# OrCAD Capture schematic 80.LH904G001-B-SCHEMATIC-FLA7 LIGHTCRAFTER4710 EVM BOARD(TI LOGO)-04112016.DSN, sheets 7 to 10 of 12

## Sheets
7 P12: Cypress USB to I2C: size D
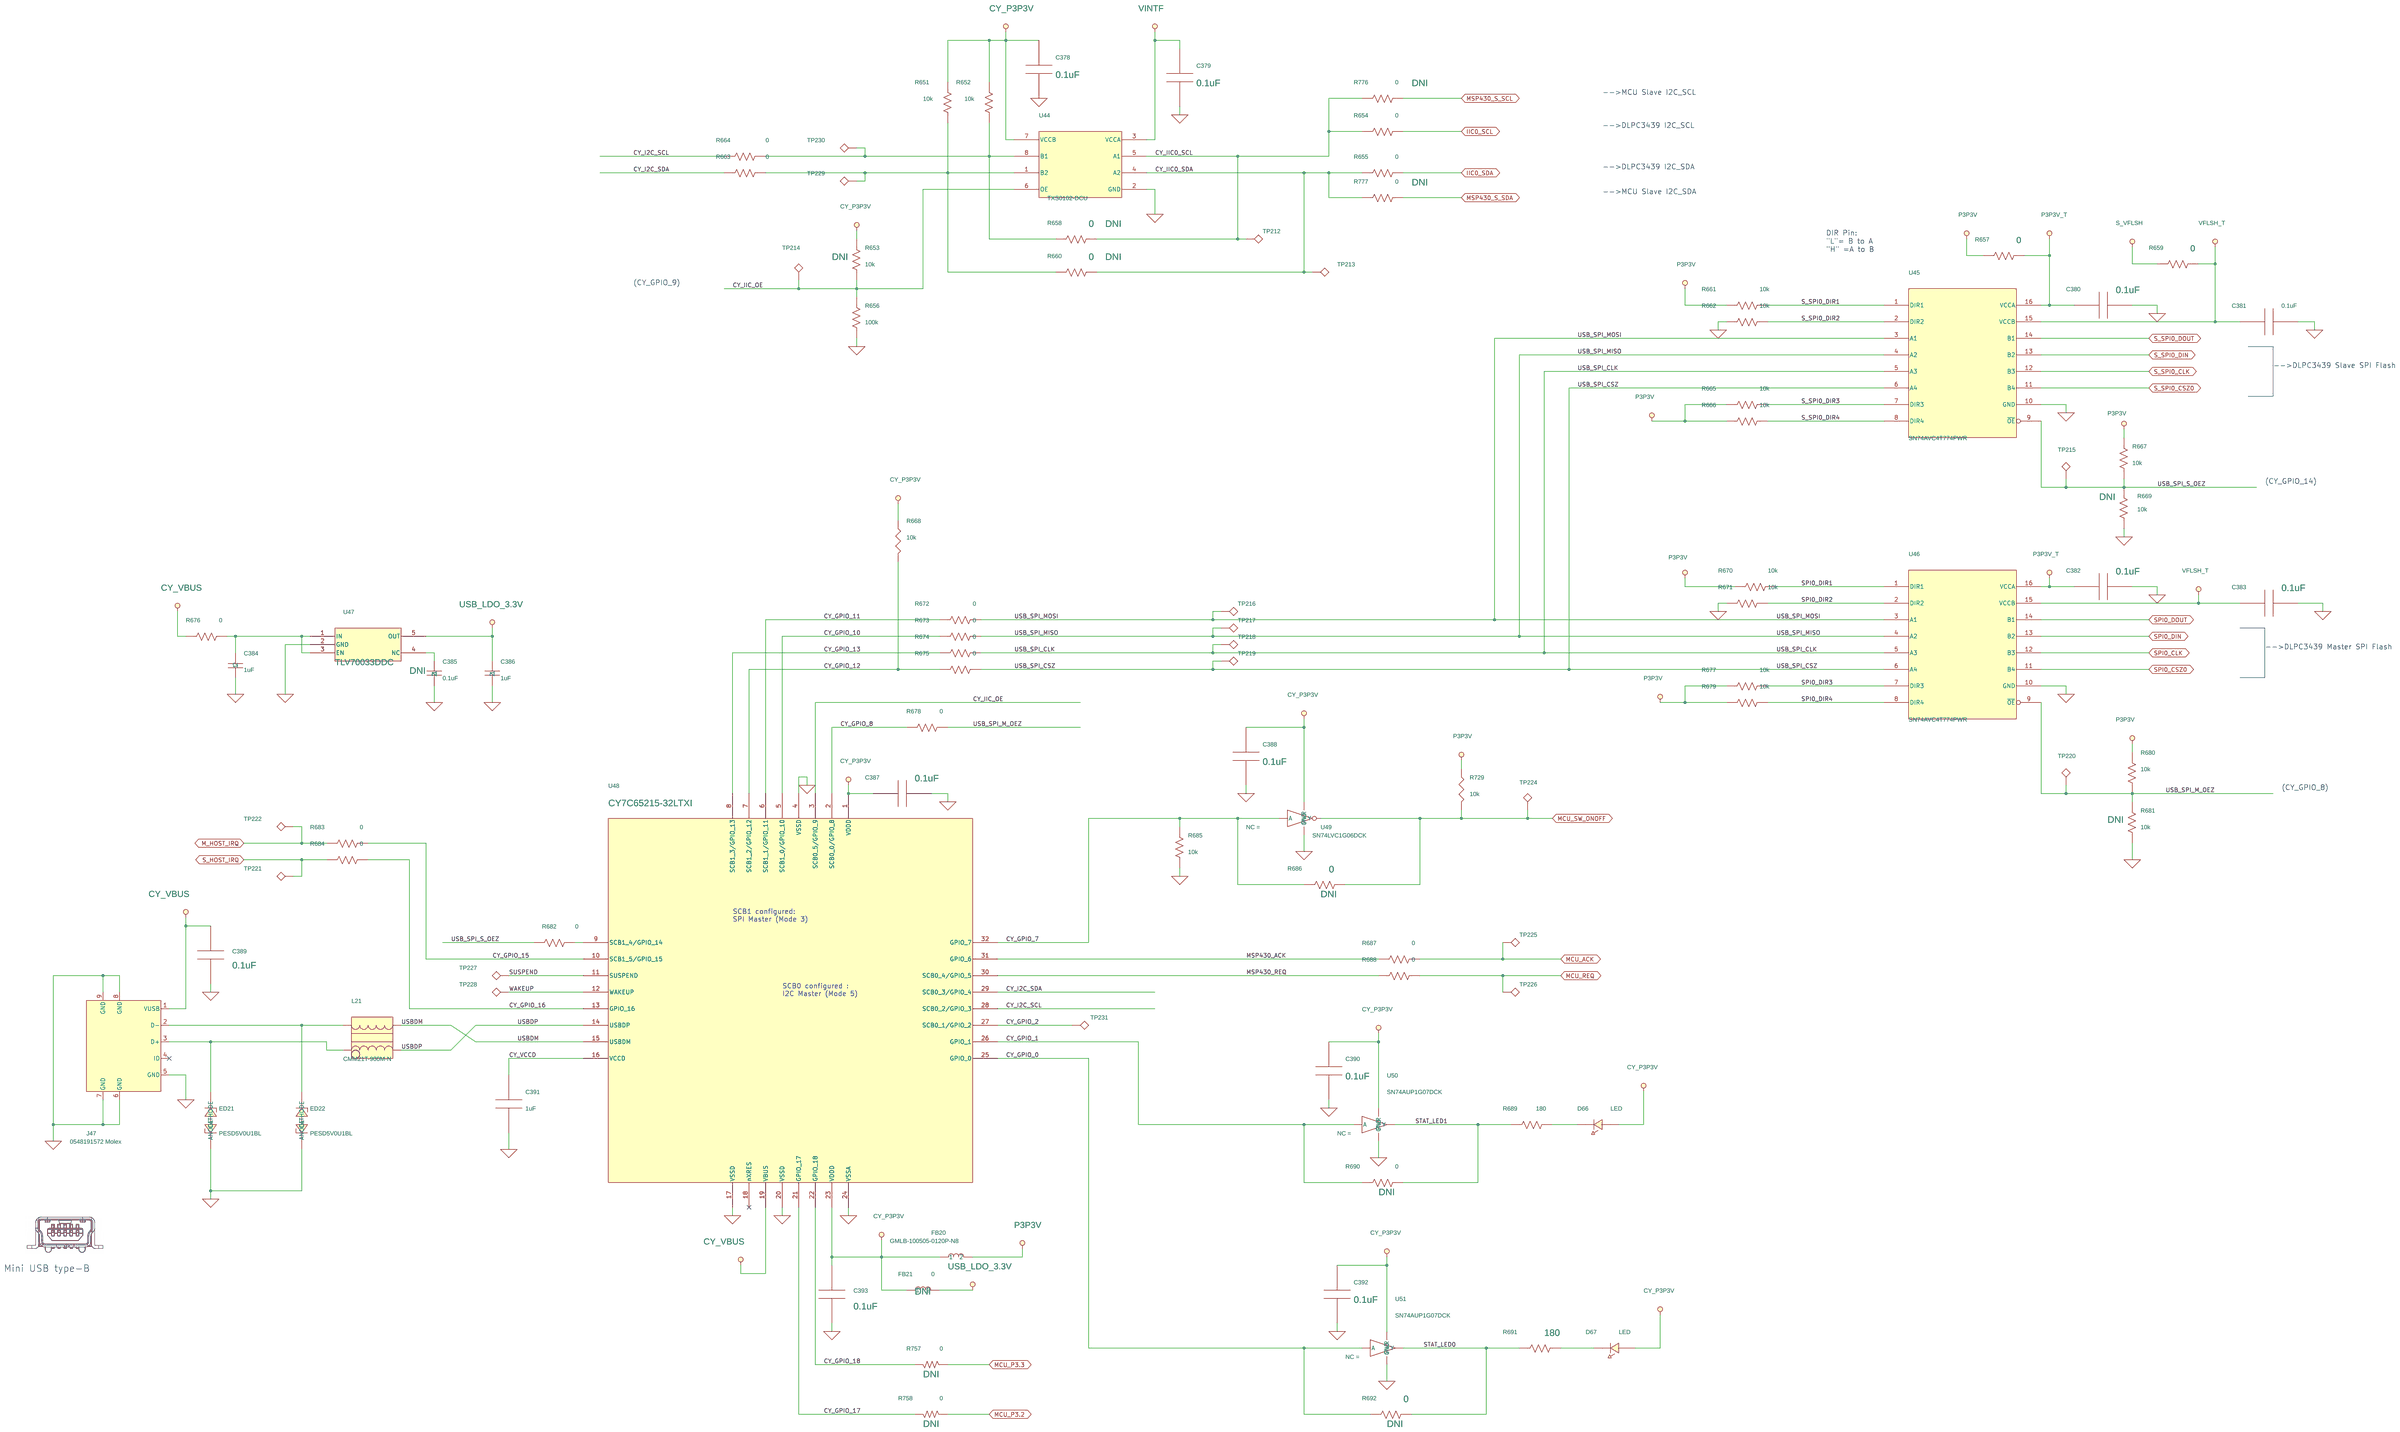
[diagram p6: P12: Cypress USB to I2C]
8 P11: Power supply and Fans: size D
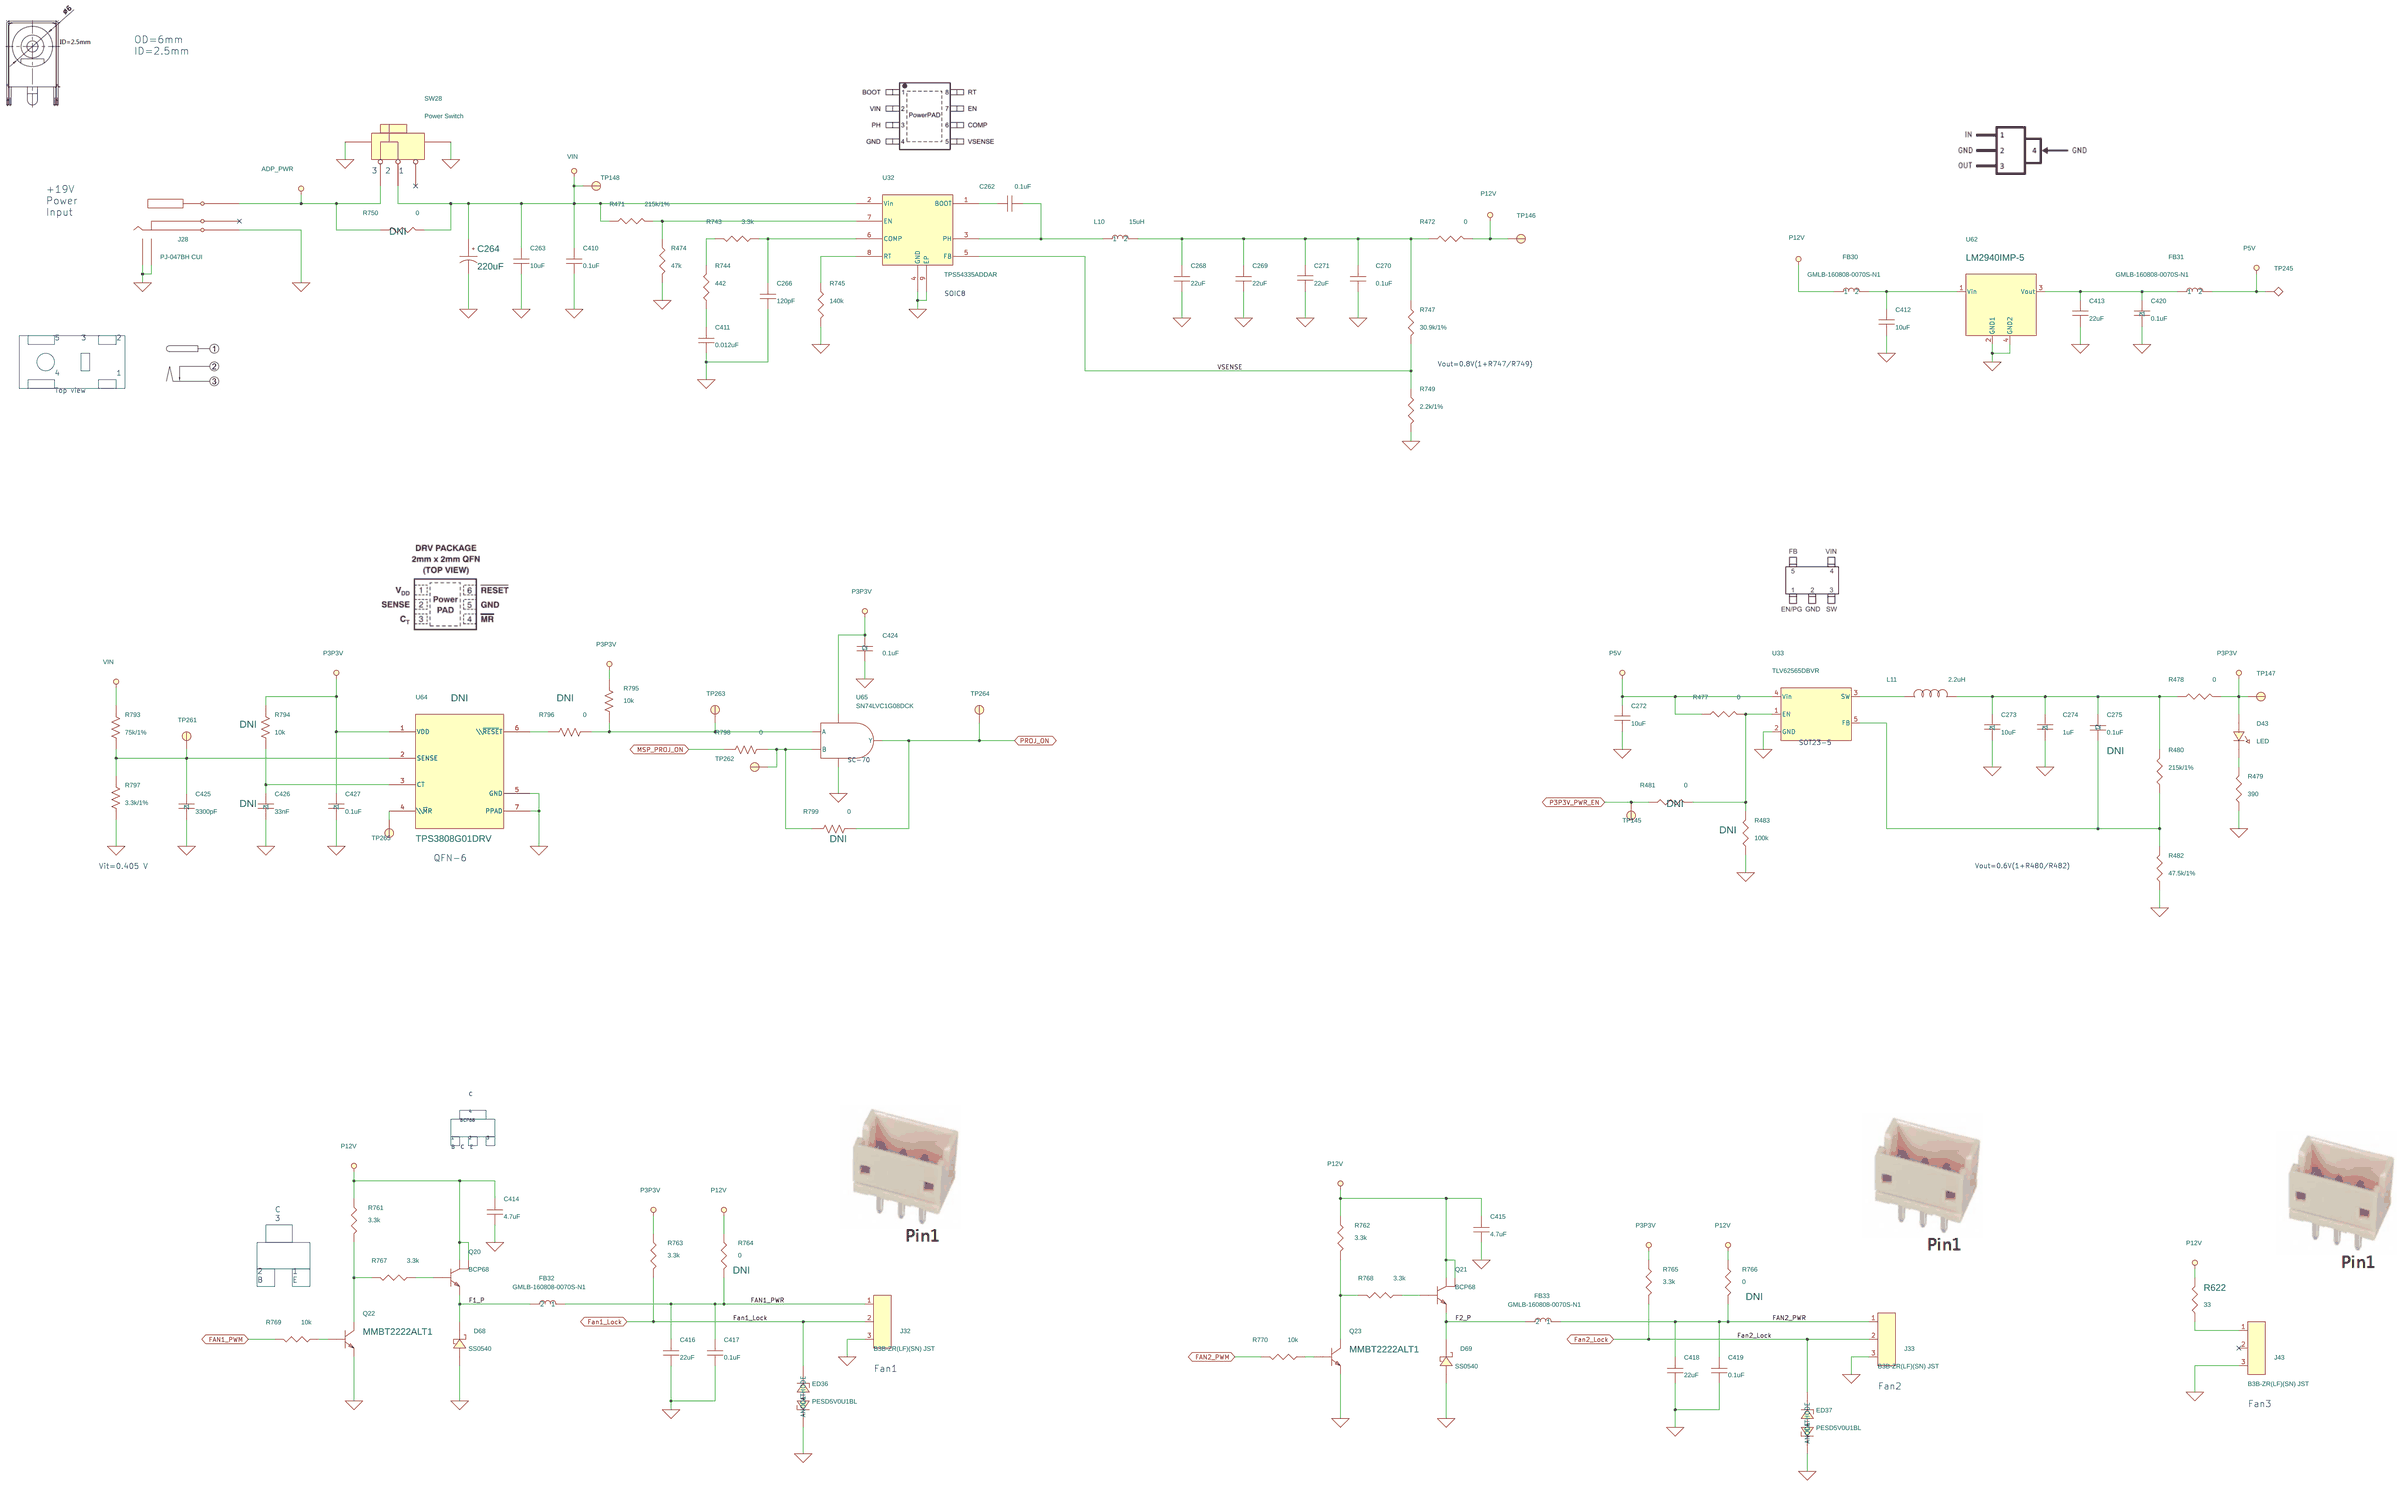
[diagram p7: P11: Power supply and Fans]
9 P04: DLPC3439_Video Input & DSI: size D
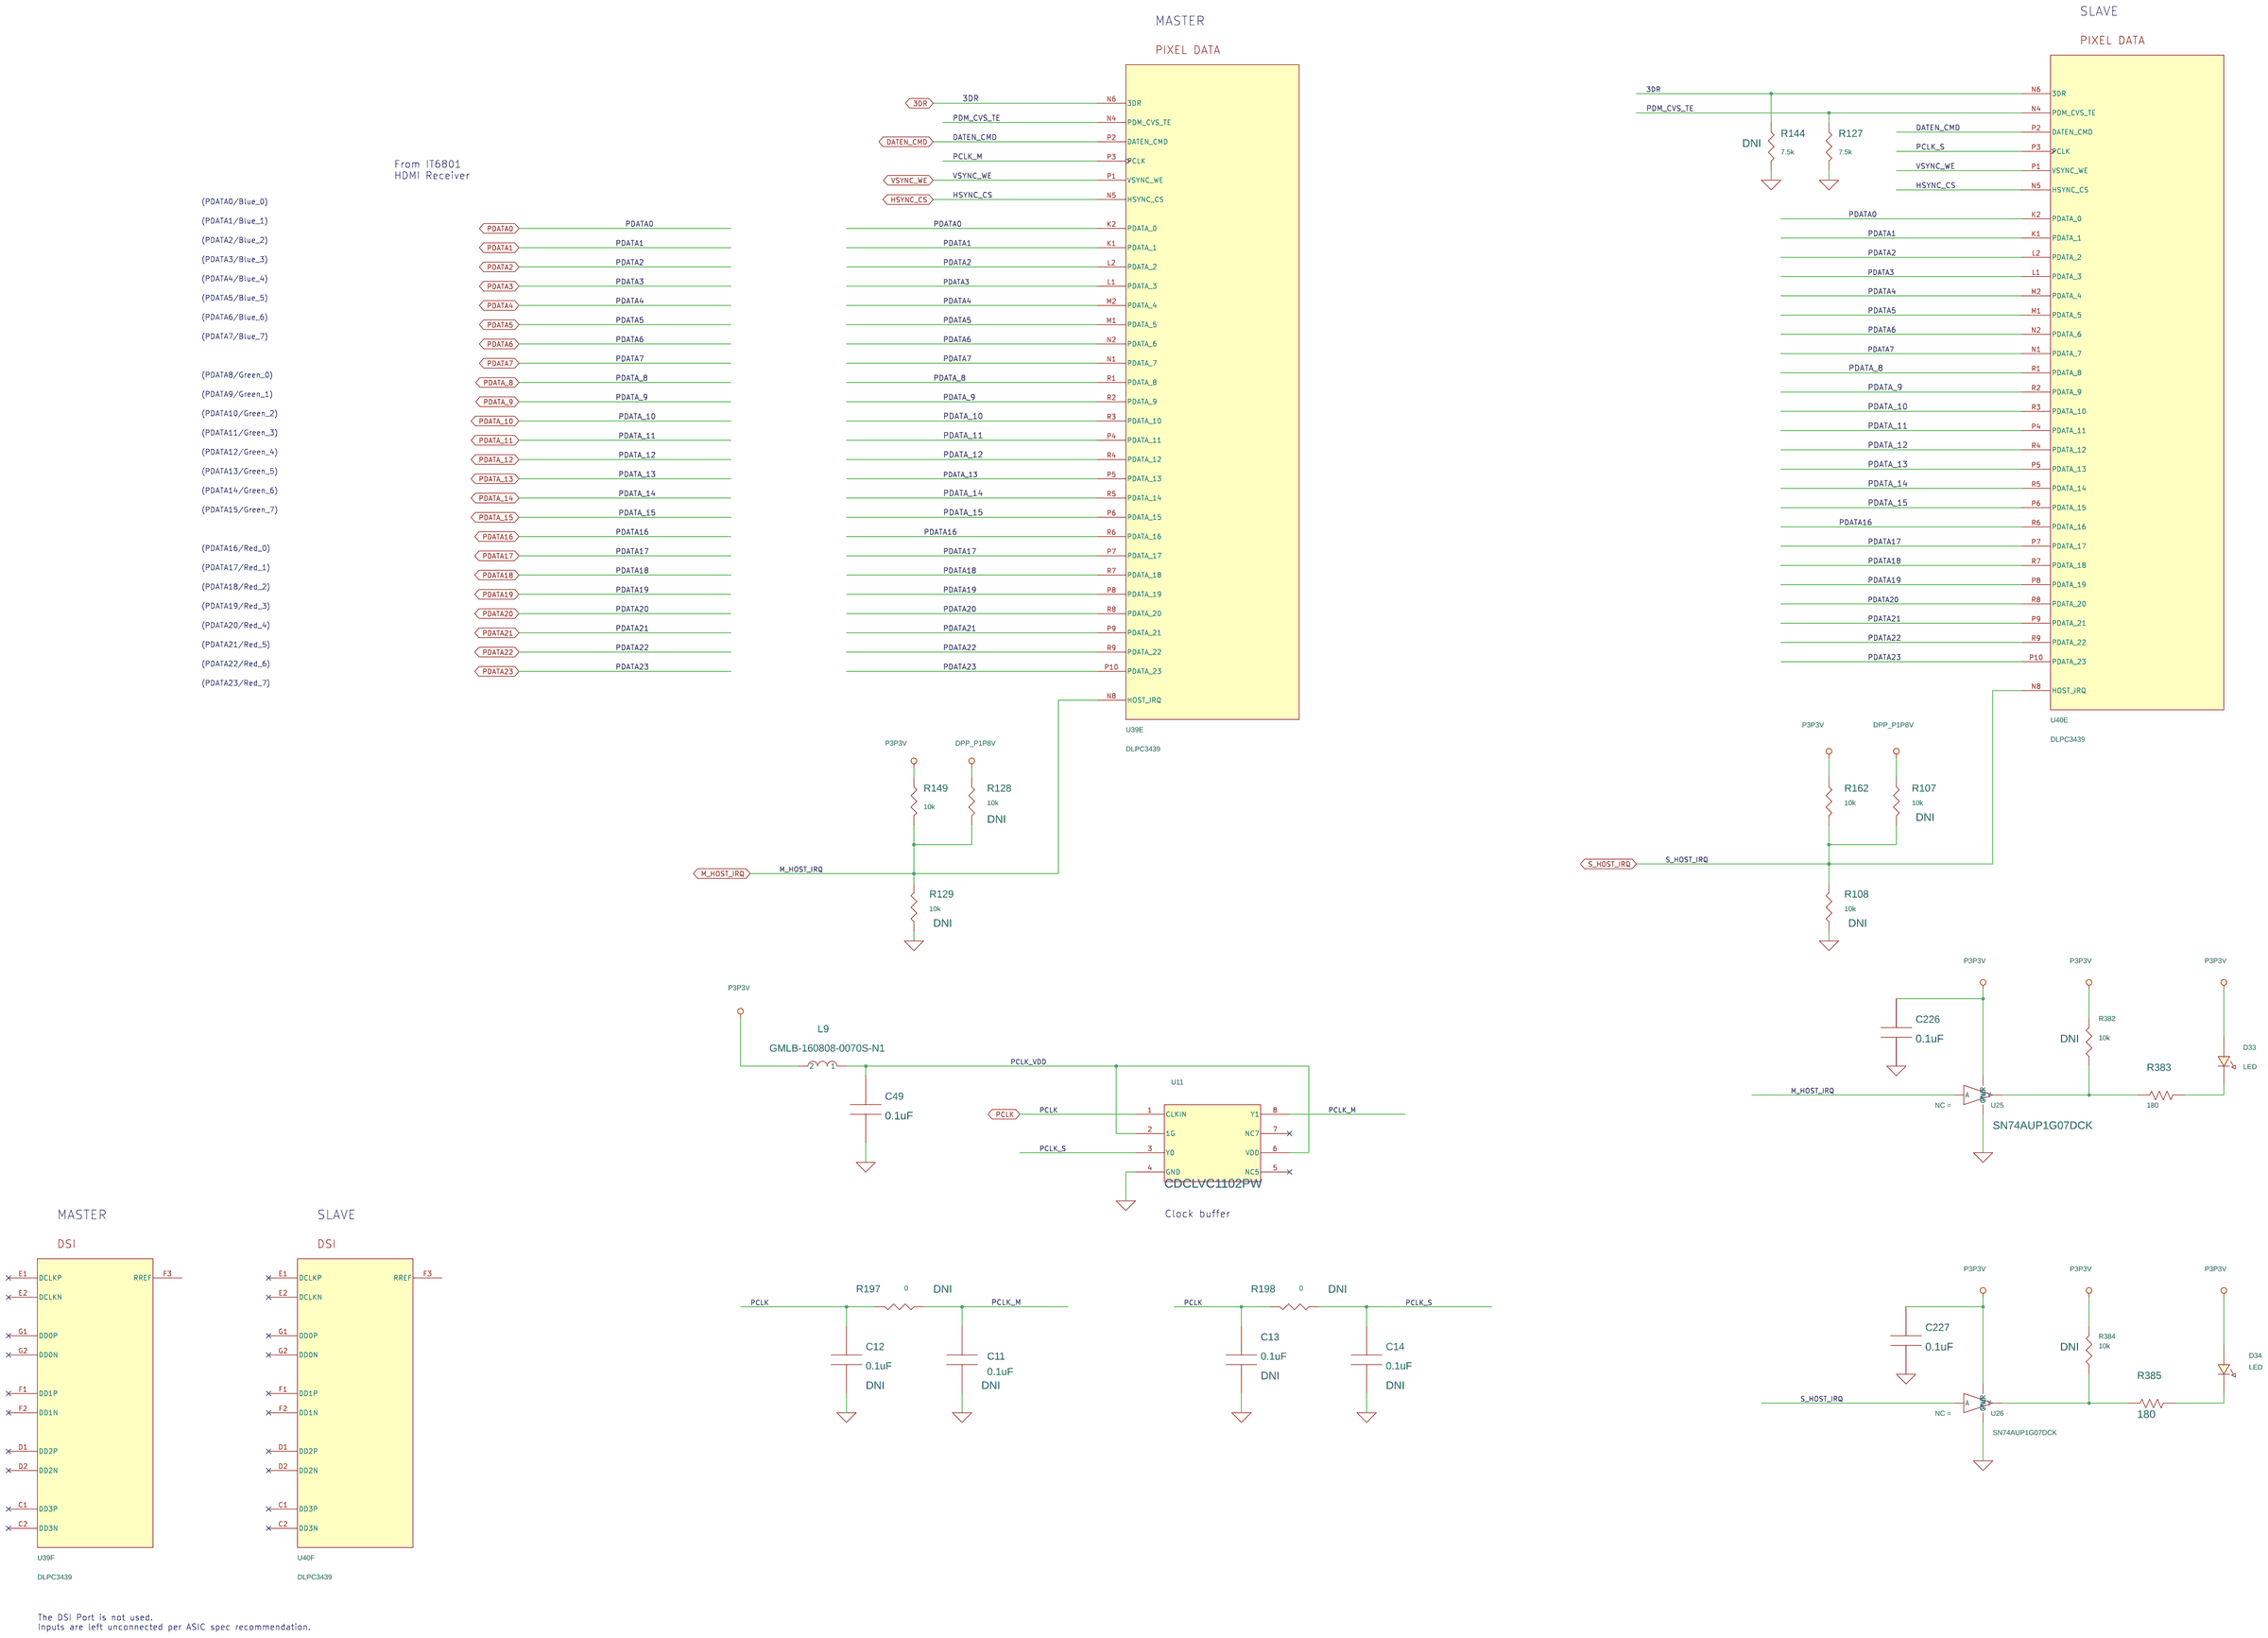
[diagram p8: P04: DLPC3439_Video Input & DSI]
10 P05: Dual DLPC343 & Flash,I2C: size D

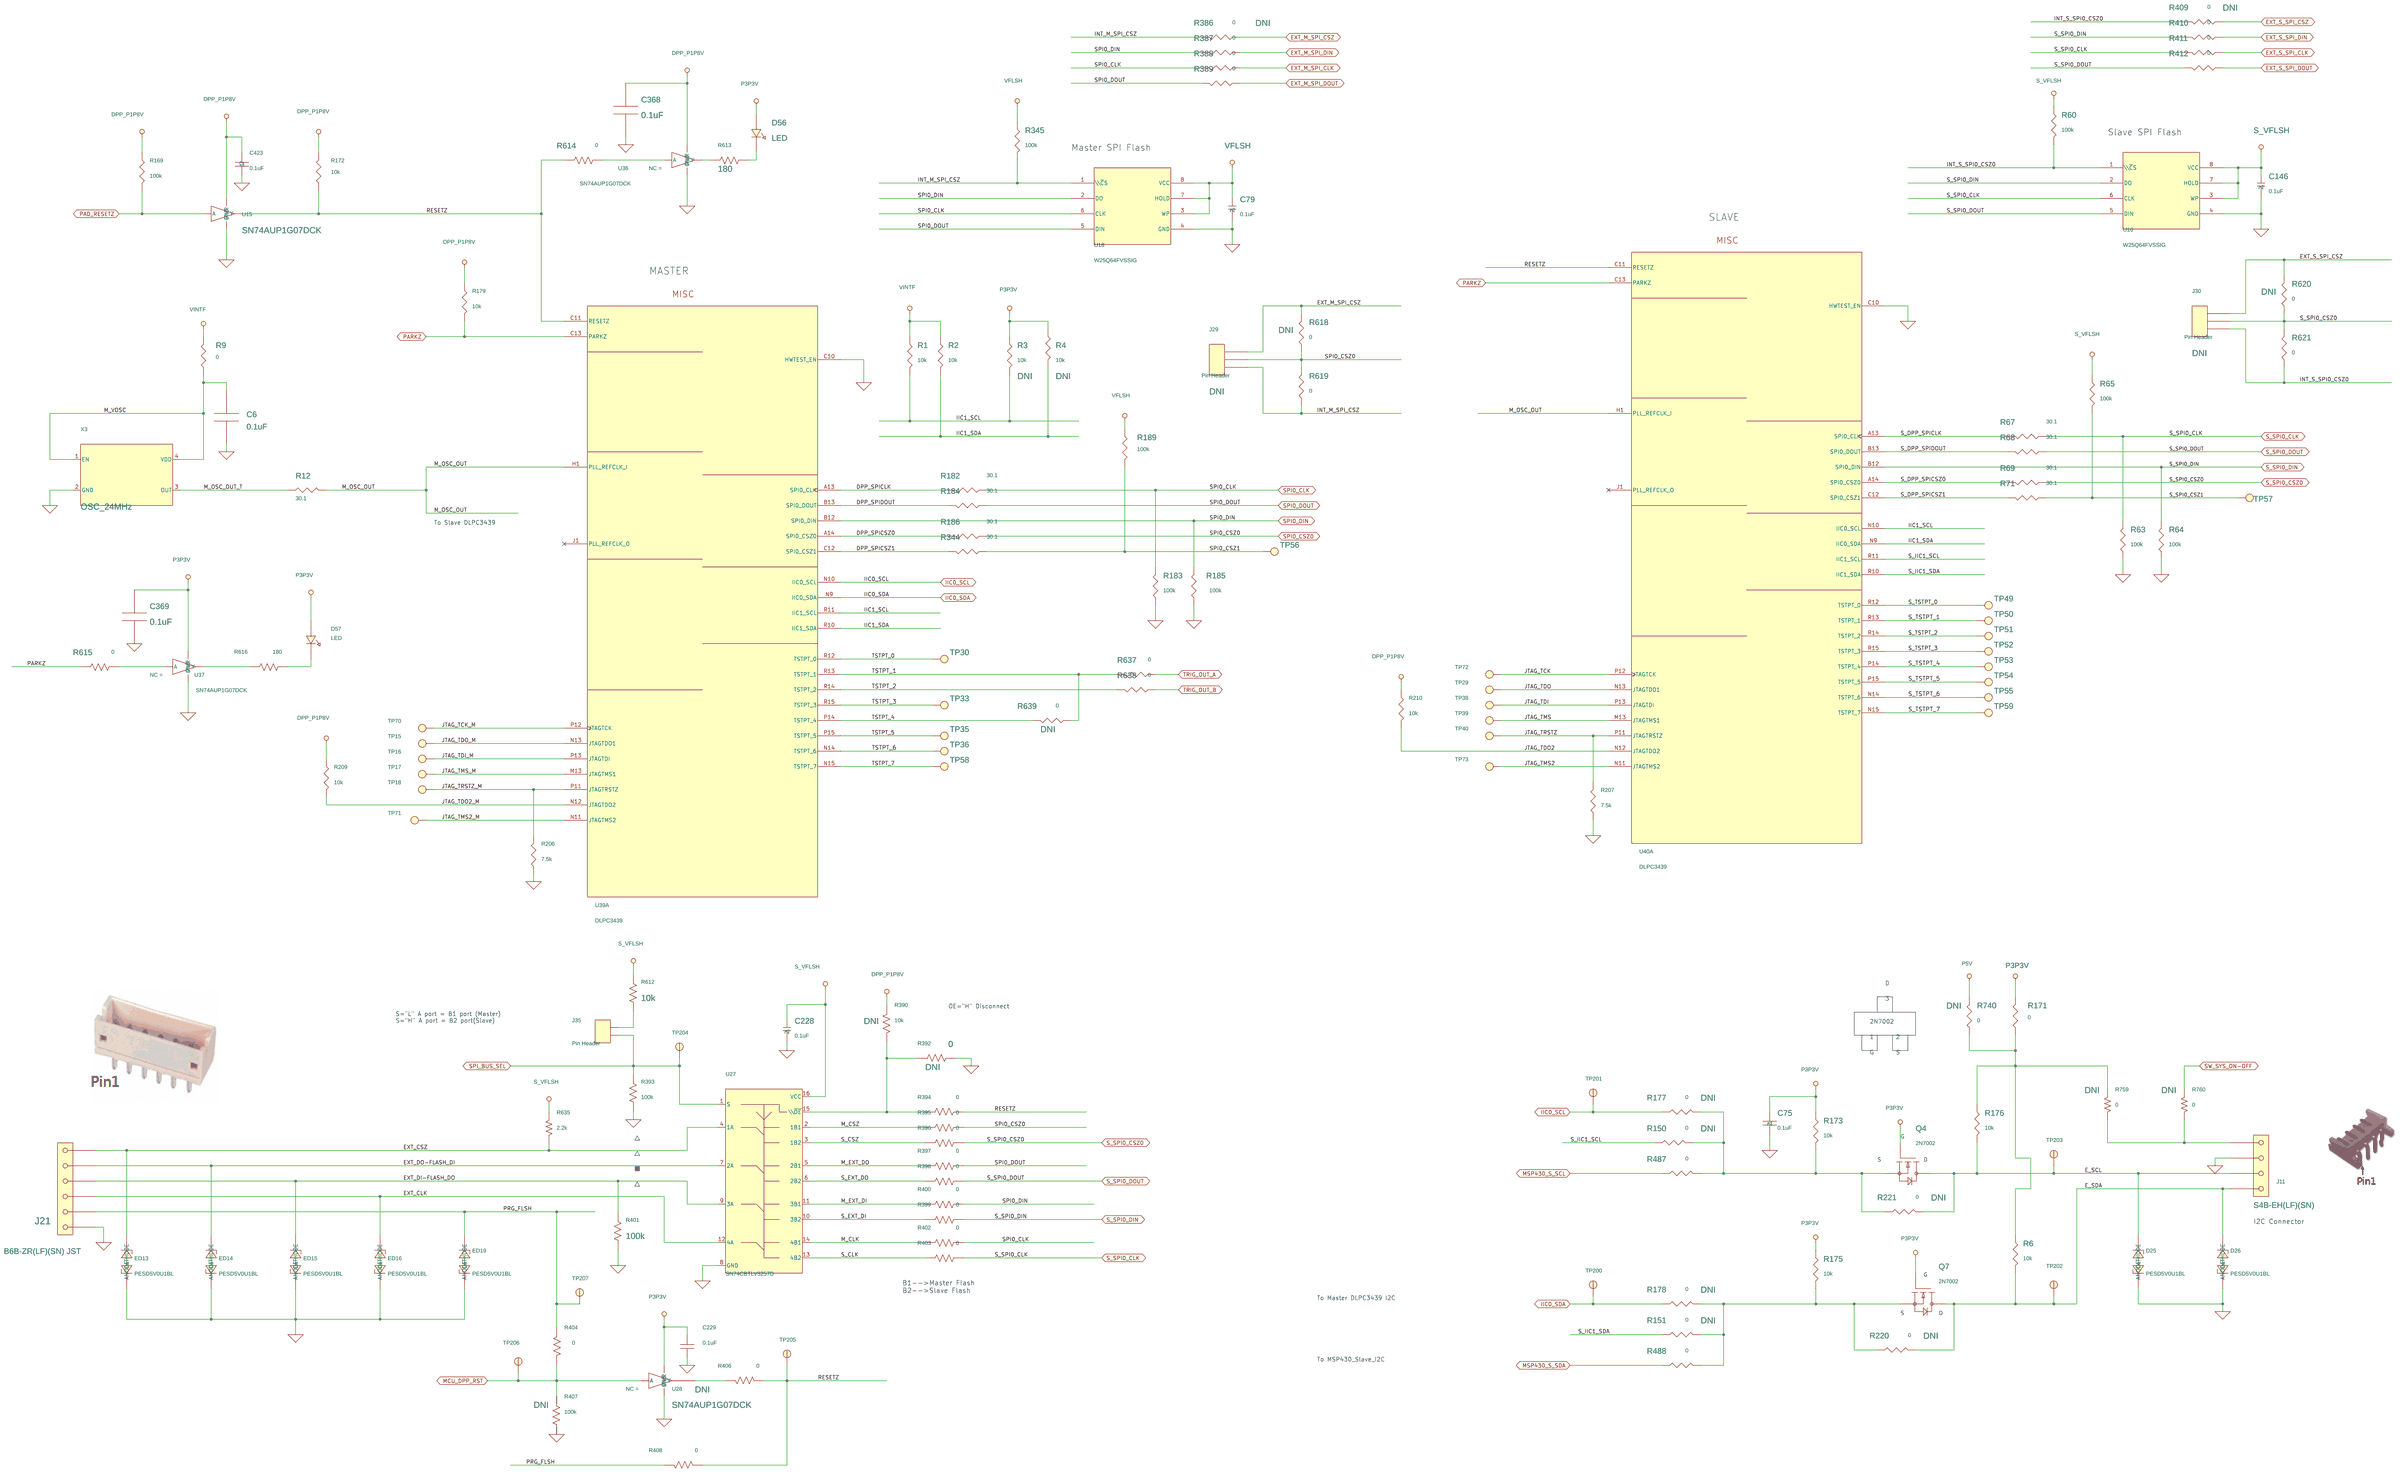
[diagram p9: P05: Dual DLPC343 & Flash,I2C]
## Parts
sheet P04: DLPC3439_Video Input & DSI
C11  0.1uF  [C0402\H0.55]
C12  0.1uF  [C0402\H0.55]
C13  0.1uF  [C0402\H0.55]
C14  0.1uF  [C0402\H0.55]
C49  0.1uF  [C0402\H0.55]
C226  0.1uF  [C0402\H0.55]
C227  0.1uF  [C0402\H0.55]
D33  LED  [LED2S\16-213\1X0.5\H0.45]
D34  LED  [LED2S\16-213\1X0.5\H0.45]
L9  GMLB-160808-0070S-N1  [L0603\H0.95]
R107  10k  [R0402\H0.4]
R108  10k  [R0402\H0.4]
R127  7.5k  [R0402\H0.4]
R128  10k  [R0402\H0.4]
R129  10k  [R0402\H0.4]
R144  7.5k  [R0402\H0.4]
R149  10k  [R0402\H0.4]
R162  10k  [R0402\H0.4]
R197  0  [R0402\H0.4]
R198  0  [R0402\H0.4]
R382  10k  [R0402\H0.4]
R383  180  [R0402\H0.4]
R384  10k  [R0402\H0.4]
R385  180  [R0402\H0.4]
U11  CDCLVC1102PW  [TSSOP8\0.65\H1.2]
U25  SN74AUP1G07DCK  [MCP5\0.65\H1.1]
U26  SN74AUP1G07DCK  [MCP5\0.65\H1.1]
sheet P05: Dual DLPC343 & Flash,I2C
C6  0.1uF  [C0402\H0.55]
C75  0.1uF  [C0402\H0.55]
C79  0.1uF  [C0201\H0.33]
C146  0.1uF  [C0201\H0.33]
C228  0.1uF  [C0201\H0.33]
C229  0.1uF  [C0402\H0.55]
C368  0.1uF  [C0402\H0.55]
C369  0.1uF  [C0402\H0.55]
C423  0.1uF  [C0402\H0.55]
D25  PESD5V0U1BL  [SOD882\2A1C\H0.5]
D26  PESD5V0U1BL  [SOD882\2A1C\H0.5]
D56  LED  [LED2S\16-213\1X0.5\H0.45]
D57  LED  [LED2S\16-213\1X0.5\H0.45]
ED13  PESD5V0U1BL  [SOD882\2A1C\H0.5]
ED14  PESD5V0U1BL  [SOD882\2A1C\H0.5]
ED15  PESD5V0U1BL  [SOD882\2A1C\H0.5]
ED16  PESD5V0U1BL  [SOD882\2A1C\H0.5]
ED19  PESD5V0U1BL  [SOD882\2A1C\H0.5]
J11  S4B-EH(LF)(SN)  [TU3007_4D_90\2.5\H4.8]
J21  B6B-ZR(LF)(SN) JST  [TU1501_6D_180\1.5\H4.5]
J29  Pin Header  [SIP3\2.54]
J30  Pin Header  [SIP3\2.54]
J35  Pin Header  [SIP2\2.54]
Q4  2N7002  [CP3\0.95\H1.11]
Q7  2N7002  [CP3\0.95\H1.11]
R1  10k  [R0402\H0.4]
R2  10k  [R0402\H0.4]
R3  10k  [R0402\H0.4]
R4  10k  [R0402\H0.4]
R6  10k  [R0402\H0.4]
R9  0  [R0402\H0.4]
R12  30.1  [R0402\H0.4]
R60  100k  [R0402\H0.4]
R63  100k  [R0402\H0.4]
R64  100k  [R0402\H0.4]
R65  100k  [R0402\H0.4]
R67  30.1  [R0402\H0.4]
R68  30.1  [R0402\H0.4]
R69  30.1  [R0402\H0.4]
R71  30.1  [R0402\H0.4]
R150  0  [R0402\H0.4]
R151  0  [R0402\H0.4]
R169  100k  [R0402\H0.4]
R171  0  [R0402\H0.4]
R172  10k  [R0402\H0.4]
R173  10k  [R0402\H0.4]
R175  10k  [R0402\H0.4]
R176  10k  [R0402\H0.4]
R177  0  [R0402\H0.4]
R178  0  [R0402\H0.4]
R179  10k  [R0402\H0.4]
R182  30.1  [R0402\H0.4]
R183  100k  [R0402\H0.4]
R184  30.1  [R0402\H0.4]
R185  100k  [R0402\H0.4]
R186  30.1  [R0402\H0.4]
R189  100k  [R0402\H0.4]
R206  7.5k  [R0402\H0.4]
R207  7.5k  [R0402\H0.4]
R209  10k  [R0402\H0.4]
R210  10k  [R0402\H0.4]
R220  0  [R0402\H0.4]
R221  0  [R0402\H0.4]
R344  30.1  [R0402\H0.4]
R345  100k  [R0402\H0.4]
R386  0  [R0402\H0.4]
R387  0  [R0402\H0.4]
R388  0  [R0402\H0.4]
R389  0  [R0402\H0.4]
R390  10k  [R0402\H0.4]
R392  0  [R0402\H0.4]
R393  100k  [R0402\H0.4]
R394  0  [R0402\H0.4]
R395  0  [R0402\H0.4]
R396  0  [R0402\H0.4]
R397  0  [R0402\H0.4]
R398  0  [R0402\H0.4]
R399  0  [R0402\H0.4]
R400  0  [R0402\H0.4]
R401  100k  [R0402\H0.4]
R402  0  [R0402\H0.4]
R403  0  [R0402\H0.4]
R404  0  [R0402\H0.4]
R406  0  [R0402\H0.4]
R407  100k  [R0402\H0.4]
R408  0  [R0402\H0.4]
R409  0  [R0402\H0.4]
R410  0  [R0402\H0.4]
R411  0  [R0402\H0.4]
R412  0  [R0402\H0.4]
R487  0  [R0402\H0.4]
R488  0  [R0402\H0.4]
R612  10k  [R0402\H0.4]
R613  180  [R0402\H0.4]
R614  0  [R0402\H0.4]
R615  0  [R0402\H0.4]
R616  180  [R0402\H0.4]
R618  0  [R0402\H0.4]
R619  0  [R0402\H0.4]
R620  0  [R0402\H0.4]
R621  0  [R0402\H0.4]
R635  2.2k  [R0402\H0.4]
R637  0  [R0402\H0.4]
R638  0  [R0402\H0.4]
R639  0  [R0402\H0.4]
R740  0  [R0402\H0.4]
R759  0  [R0402\H0.4]
R760  0  [R0402\H0.4]
TP15  Testpoint  [ICT_50]
TP16  Testpoint  [ICT_50]
TP17  Testpoint  [ICT_50]
TP18  Testpoint  [ICT_50]
TP29  Testpoint  [ICT_50]
TP30  Testpoint  [ICT_50]
TP33  Testpoint  [ICT_50]
TP35  Testpoint  [ICT_50]
TP36  Testpoint  [ICT_50]
TP38  Testpoint  [ICT_50]
TP39  Testpoint  [ICT_50]
TP40  Testpoint  [ICT_50]
TP49  Testpoint  [ICT_50]
TP50  Testpoint  [ICT_50]
TP51  Testpoint  [ICT_50]
TP52  Testpoint  [ICT_50]
TP53  Testpoint  [ICT_50]
TP54  Testpoint  [ICT_50]
TP55  Testpoint  [ICT_50]
TP56  Testpoint  [ICT_50]
TP57  Testpoint  [ICT_50]
TP58  Testpoint  [ICT_50]
TP59  Testpoint  [ICT_50]
TP70  Testpoint  [ICT_50]
TP71  Testpoint  [ICT_50]
TP72  Testpoint  [ICT_50]
TP73  Testpoint  [ICT_50]
TP200  Testpoint  [ICT_50]
TP201  Testpoint  [ICT_50]
TP202  Testpoint  [ICT_50]
TP203  Testpoint  [ICT_50]
TP204  Testpoint  [ICT_50]
TP205  Testpoint  [ICT_50]
TP206  Testpoint  [ICT_50]
TP207  Testpoint  [ICT_50]
U15  SN74AUP1G07DCK  [MCP5\0.65\H1.1]
U16  W25Q64FVSSIG  [SOP8A\1.27\H2.16]
U18  W25Q64FVSSIG  [SOP8A\1.27\H2.16]
U27  SN74CBTLV3257D  [SOP16A\1.27\H1.75]
U28  SN74AUP1G07DCK  [MCP5\0.65\H1.1]
U36  SN74AUP1G07DCK  [MCP5\0.65\H1.1]
U37  SN74AUP1G07DCK  [MCP5\0.65\H1.1]
X3  OSC_24MHz  [CRYS4\SO3225\3.2X2.5\H1.2]
sheet P06: DLPC3439_GPIO,LED_SEL,TRIG
U39  DLPC3439  [VFBGA201\0.8\H1]  (sections A,B,C,D,E,F,G,H)
U40  DLPC3439  [VFBGA201\0.8\H1]  (sections A,B,C,D,E,F,G,H)
sheet P11: Power supply and Fans
C262  0.1uF  [C0603\H0.9]
C263  10uF  [C1210\H2.8]
C264  220uF  [CS\MR10\H10.5]
C266  120pF  [C0402\H0.55]
C268  22uF  [C1210\H2.8]
C269  22uF  [C1210\H2.8]
C270  0.1uF  [C0402\H0.55]
C271  22uF  [C1210\H2.8]
C272  10uF  [C0603\H0.9]
C273  10uF  [C0603\H0.9]
C274  1uF  [C0402\H0.55]
C275  0.1uF  [C0402\H0.55]
C410  0.1uF  [C0603\H0.9]
C411  0.012uF  [C0603\H0.9]
C412  10uF  [C0805\H1.35]
C413  22uF  [C0805\H1.35]
C414  4.7uF  [C0805\H1.35]
C415  4.7uF  [C0805\H1.35]
C416  22uF  [C1210\H2.8]
C417  0.1uF  [C0402\H0.55]
C418  22uF  [C1210\H2.8]
C419  0.1uF  [C0402\H0.55]
C420  0.1uF  [C0402\H0.55]
C424  0.1uF  [C0402\H0.55]
C425  3300pF  [C0402\H0.55]
C426  33nF  [C0402\H0.55]
C427  0.1uF  [C0402\H0.55]
D43  LED  [LED2S\16-213\1X0.5\H0.45]
D68  SS0540  [SOD123\3.85X1.8\H1.35]
D69  SS0540  [SOD123\3.85X1.8\H1.35]
ED36  PESD5V0U1BL  [SOD882\2A1C\H0.5]
ED37  PESD5V0U1BL  [SOD882\2A1C\H0.5]
FB30  GMLB-160808-0070S-N1  [L0603\H0.95]
FB31  GMLB-160808-0070S-N1  [L0603\H0.95]
FB32  GMLB-160808-0070S-N1  [L0603\H0.95]
FB33  GMLB-160808-0070S-N1  [L0603\H0.95]
J28  PJ-047BH CUI  [DC-JACK3\IDJ-D40-D43B2\H9.6]
J32  B3B-ZR(LF)(SN) JST  [SSIP3\1.5\H4.5]
J33  B3B-ZR(LF)(SN) JST  [SSIP3\1.5\H4.5]
J43  B3B-ZR(LF)(SN) JST  [SSIP3\1.5\H4.5]
L10  15uH  [IND\MMD-10DZ\H4]
L11  2.2uH  [IND\3X3\H1.5]
Q20  BCP68  [SOT223\2.3\H1.8]
Q21  BCP68  [SOT223\2.3\H1.8]
Q22  MMBT2222ALT1  [CPH3A\0.95\H1.25]
Q23  MMBT2222ALT1  [CPH3A\0.95\H1.25]
R471  215k/1%  [R0402\H0.4]
R472  0  [R1206\H0.65]
R474  47k  [R0402\H0.4]
R477  0  [R0402\H0.4]
R478  0  [R0402\H0.4]
R479  390  [R0402\H0.4]
R480  215k/1%  [R0402\H0.4]
R481  0  [R0402\H0.4]
R482  47.5k/1%  [R0402\H0.4]
R483  100k  [R0402\H0.4]
R622  33  [R0402\H0.4]
R743  3.3k  [R0402\H0.4]
R744  442  [R0603\H0.55]
R745  140k  [R0603\H0.55]
R747  30.9k/1%  [R0402\H0.4]
R749  2.2k/1%  [R0402\H0.4]
R750  0  [R1206\H0.65]
R761  3.3k  [R0402\H0.4]
R762  3.3k  [R0402\H0.4]
R763  3.3k  [R0402\H0.4]
R764  0  [R0402\H0.4]
R765  3.3k  [R0402\H0.4]
R766  0  [R0402\H0.4]
R767  3.3k  [R0402\H0.4]
R768  3.3k  [R0402\H0.4]
R769  10k  [R0402\H0.4]
R770  10k  [R0402\H0.4]
R793  75k/1%  [R0402\H0.4]
R794  10k  [R0402\H0.4]
R795  10k  [R0402\H0.4]
R796  0  [R0402\H0.4]
R797  3.3k/1%  [R0402\H0.4]
R798  0  [R0402\H0.4]
R799  0  [R0402\H0.4]
SW28  Power Switch  [SW3D\TS-13P-A1\H6.6]
TP145  Testpoint  [ICT_50]
TP146  Testpoint  [ICT_50]
TP147  Testpoint  [ICT_50]
TP148  Testpoint  [ICT_50]
TP245  Testpoint  [ICT_50]
TP261  Testpoint  [ICT_50]
TP262  Testpoint  [ICT_50]
TP263  Testpoint  [ICT_50]
TP264  Testpoint  [ICT_50]
TP265  Testpoint  [ICT_50]
U32  TPS54335ADDAR  [SOP8B\1.27\H1.75]
U33  TLV62565DBVR  [CP5\0.95\H1.45]
U62  LM2940IMP-5  [SOT223\2.3\H1.8]
U64  TPS3808G01DRV  [SON6\DRV\0.65\H0.8]
U65  SN74LVC1G08DCK  [MCP5\0.65\H1.1]
sheet P12: Cypress USB to I2C
C378  0.1uF  [C0402\H0.55]
C379  0.1uF  [C0402\H0.55]
C380  0.1uF  [C0402\H0.55]
C381  0.1uF  [C0402\H0.55]
C382  0.1uF  [C0402\H0.55]
C383  0.1uF  [C0402\H0.55]
C384  1uF  [C0402\H0.55]
C385  0.1uF  [C0402\H0.55]
C386  1uF  [C0402\H0.55]
C387  0.1uF  [C0402\H0.55]
C388  0.1uF  [C0402\H0.55]
C389  0.1uF  [C0402\H0.55]
C390  0.1uF  [C0402\H0.55]
C391  1uF  [C0402\H0.55]
C392  0.1uF  [C0402\H0.55]
C393  0.1uF  [C0402\H0.55]
D66  LED  [LED2S\16-213\1X0.5\H0.45]
D67  LED  [LED2S\16-213\1X0.5\H0.45]
ED21  PESD5V0U1BL  [SOD882\2A1C\H0.5]
ED22  PESD5V0U1BL  [SOD882\2A1C\H0.5]
FB20  GMLB-100505-0120P-N8  [L0402\H0.6]
FB21  0  [L0402\H0.6]
J47  0548191572 Molex  [USB5A\0.8\H4.1]
L21  CMM21T-900M-N  [L\MCI-2012-900\H1.4]
R651  10k  [R0402\H0.4]
R652  10k  [R0402\H0.4]
R653  10k  [R0402\H0.4]
R654  0  [R0402\H0.4]
R655  0  [R0402\H0.4]
R656  100k  [R0402\H0.4]
R657  0  [R0402\H0.4]
R658  0  [R0402\H0.4]
R659  0  [R0402\H0.4]
R660  0  [R0402\H0.4]
R661  10k  [R0402\H0.4]
R662  10k  [R0402\H0.4]
R663  0  [R0402\H0.4]
R664  0  [R0402\H0.4]
R665  10k  [R0402\H0.4]
R666  10k  [R0402\H0.4]
R667  10k  [R0402\H0.4]
R668  10k  [R0402\H0.4]
R669  10k  [R0402\H0.4]
R670  10k  [R0402\H0.4]
R671  10k  [R0402\H0.4]
R672  0  [R0402\H0.4]
R673  0  [R0402\H0.4]
R674  0  [R0402\H0.4]
R675  0  [R0402\H0.4]
R676  0  [R0402\H0.4]
R677  10k  [R0402\H0.4]
R678  0  [R0402\H0.4]
R679  10k  [R0402\H0.4]
R680  10k  [R0402\H0.4]
R681  10k  [R0402\H0.4]
R682  0  [R0402\H0.4]
R683  0  [R0402\H0.4]
R684  0  [R0402\H0.4]
R685  10k  [R0402\H0.4]
R686  0  [R0402\H0.4]
R687  0  [R0402\H0.4]
R688  0  [R0402\H0.4]
R689  180  [R0402\H0.4]
R690  0  [R0402\H0.4]
R691  180  [R0402\H0.4]
R692  0  [R0402\H0.4]
R729  10k  [R0402\H0.4]
R757  0  [R0402\H0.4]
R758  0  [R0402\H0.4]
R776  0  [R0402\H0.4]
R777  0  [R0402\H0.4]
TP212  Testpoint  [ICT_50]
TP213  Testpoint  [ICT_50]
TP214  Testpoint  [ICT_50]
TP215  Testpoint  [ICT_50]
TP216  Testpoint  [ICT_50]
TP217  Testpoint  [ICT_50]
TP218  Testpoint  [ICT_50]
TP219  Testpoint  [ICT_50]
TP220  Testpoint  [ICT_50]
TP221  Testpoint  [ICT_50]
TP222  Testpoint  [ICT_50]
TP224  Testpoint  [ICT_50]
TP225  Testpoint  [ICT_50]
TP226  Testpoint  [ICT_50]
TP227  Testpoint  [ICT_50]
TP228  Testpoint  [ICT_50]
TP229  Testpoint  [ICT_50]
TP230  Testpoint  [ICT_50]
TP231  Testpoint  [ICT_50]
U44  TXS0102-DCU  [MSOP8\0.5\H0.9]
U45  SN74AVC4T774PWR  [TSSOP16\0.65\H1.2]
U46  SN74AVC4T774PWR  [TSSOP16\0.65\H1.2]
U47  TLV70033DDC  [CP5\0.95\H1.3]
U48  CY7C65215-32LTXI  [QFN32\T\0.5\H1]
U49  SN74LVC1G06DCK  [MCP5\0.65\H1.1]
U50  SN74AUP1G07DCK  [MCP5\0.65\H1.1]
U51  SN74AUP1G07DCK  [MCP5\0.65\H1.1]

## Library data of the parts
C11-C14 = PAS,CAP,NP,large: DNI: DNI; DigiKey: 490-3261-1-ND; DigiReel: 490-3261-6-ND; Family: passive; Index PN: 681; Lead Style: SMT; MFG: Murata; Material: x7r; P/D_NUM: GRM155R71C104KA88D; Part Number: GRM155R71C104KA88D; Part Specific: CAP CER .1UF 16V X7R 0402; TOLERANCE: 10%; Type: capacitor; VENDOR: Murata; VPC: 16V
C49 = PAS,CAP,NP,large: DigiKey: 445-13284-1-ND; DigiReel: 445-13284-6-ND; Family: passive; Index PN: 1206; Install: DNI; Lead Style: SMT; MFG: TDK; Material: npo; P/D_NUM: CGJ2B2C0G1H090D050BA; Part Number: CGJ2B2C0G1H090D050BA; Part Specific: CAP CER 9PF 50V NP0 0402; Type: capacitor; VENDOR: TDK; VPC: 50V
C6 C226 C227 C368 C369 C378-C383 C387-C390 C392 C393 = PAS,CAP,NP,large: DigiKey: 445-4952-1-ND; DigiReel: 445-4952-6-ND; Family: passive; Index PN: 681; Lead Style: SMT; MFG: TDK; Material: x7r; P/D_NUM: C1005X7R1C104K050BC; Part Number: C1005X7R1C104K050BC; Part Specific: CAP CER .1UF 16V X7R 0402; TOLERANCE: 10%; Type: capacitor; VENDOR: TDK; VPC: 16V
D33 D34 D43 D56 D57 D66 D67 = DSEI20_TO_0
L9 = INDUCTOR_0: INDUCTOR; Package: SMD 1210; Vendor: Taiyo Yuden/Any
R3 R4 R107 R108 R128 R129 R144 R150 R151 R177 R178 R197 R198 R220 R221 R382 R384 R386 R409 R481 R618 R620 R639 R740 = RESISTOR_SM: DNI: DNI
R1 R2 R6 R9 R12 R60 R63-R65 R67-R69 R71 R127 R149 R162 R169 R171-R173 R175 R176 R179 R182-R186 R189 R206 R207 R209 R210 R344 R345 R387-R389 R410-R412 R471 R474 R477 R478 R487 R488 R619 R621 R622 R637 R638 R747 = RESISTOR_SM
R383 R385 R613-R616 R654 R655 R663 R664 R673 R676 R678 R682-R684 R687-R689 R691 = PAS,R,large: DigiKey: P100LCT-ND; DigiReel: P100LDKR-ND; Family: passive; Index PN: 690; Lead Style: SMT; MFG: Panasonic; Material: chip; P/D_NUM: ERJ-2RKF1000X; Part Number: ERJ-2RKF1000X; Part Specific: RES 100 OHM 1/10W 1% 0402 SMD; Power: 1/16W; TOLERANCE: 1%; Type: resistor; VENDOR: Panasonic; VPC: 1/16W
U11 = CDCLVC1102_4: DigiKey: 296-27610-1-ND; DigiReel: 296-27610-6-ND; Family: logic; Install: Y; Lead Style: SMT; MFG: Texas Instruments; P/D_NUM: CDCLVC1102PWR; Part Number: CDCLVC1102PWR; Part Specific: IC CLK BUFFER 1:2 250MHZ 8TSSOP; Pin Cnt: 8; Type: buffer; VENDOR: Texas Instruments
U25 U26 U36 U37 U50 U51 = LOG,BUF,OPENDRN,SN74AUP1G07DCK: DigiKey: 296-18256-1-ND; DigiReel: 296-18256-6-ND; Family: logic; Index PN: 1027; Install: Y; Lead Style: SMT; MFG: Texas Instruments; P/D_NUM: SN74AUP1G07DCKR; Part Number: SN74AUP1G07DCKR; Part Specific: IC BUFF/DVR LOW PWR N-INV SC705, open drain; Type: buffer
C75 C273 = CAP_0.1uF_0603_1: Ceramic CAP X7R 6.3V 0.1uF
C79 = C_1_1
C146 = C_1_2
C228 = C_1
C229 = CAP_NP: Capacitor; MFG: KEMET; Part Number: C0402C104K8RACTU; RATING: 10V; SOURCE: DIGI 399-3520-1-ND; TOLERANCE: 10%; Type: X7R
C274 C386 C423 = CAP_0.1uF_0603: Ceramic CAP X7R 6.3V 0.1uF
D25 D26 ED13-ED16 ED19 ED21 ED22 ED36 ED37 = DIODE_SCHOTTKY31_4
J11 = 3_PIN_Connector_2: Package: NC/TU1501WNV-04; SPEC.1: 1A
J21 = 3_PIN_Connector_1: Package: NC/TU1501WNV-04; SPEC.1: 1A
J29 J30 = CON3: DNI: DNI
J35 = CON2
Q4 Q7 = 2N7002
R390 R669 R681 = PAS,R,large: DNI: DNI; DigiKey: P100KLCT-ND; DigiReel: P100KLDKR-ND; Family: passive; Index PN: 712; Lead Style: SMT; MFG: Panasonic; Material: chip; P/D_NUM: ERJ-2RKF1003X; Part Number: ERJ-2RKF1003X; Part Specific: RES 100K OHM 1/10W 1% 0402 SMD; Power: 1/16W; TOLERANCE: 1%; Type: resistor; VENDOR: Panasonic; VPC: 1/16W
R392 = PAS,R,large: DNI: DNI; DigiKey: P30.1LCT-ND; DigiReel: P30.1LDKR-ND; Family: passive; Index PN: 976; Lead Style: SMT; MFG: Panasonic; Material: chip; P/D_NUM: ERJ-2RKF30R1X; Part Number: ERJ-2RKF30R1X; Part Specific: RES 30.1 OHM 1/16W 1% 0402 SMD; Power: 1/16W; TOLERANCE: 1%; Type: resistor; VPC: 1/16W; Vendor: Panasonic
R393 R401 R612 R656 = PAS,R,large: DigiKey: P100KLCT-ND; DigiReel: P100KLDKR-ND; Family: passive; Index PN: 712; Lead Style: SMT; MFG: Panasonic; Material: chip; P/D_NUM: ERJ-2RKF1003X; Part Number: ERJ-2RKF1003X; Part Specific: RES 100K OHM 1/10W 1% 0402 SMD; Power: 1/16W; TOLERANCE: 1%; Type: resistor; VENDOR: Panasonic; VPC: 1/16W
R394-R400 R403 R672 R674 R675 = PAS,R,large: DigiKey: P30.1LCT-ND; DigiReel: P30.1LDKR-ND; Family: passive; Index PN: 976; Lead Style: SMT; MFG: Panasonic; Material: chip; P/D_NUM: ERJ-2RKF30R1X; Part Number: ERJ-2RKF30R1X; Part Specific: RES 30.1 OHM 1/16W 1% 0402 SMD; Power: 1/16W; TOLERANCE: 1%; Type: resistor; VPC: 1/16W; Vendor: Panasonic
R402 = PAS,R,large: DigiKey: P0.0JCT-ND; DigiReel: P0.0JDKR-ND; Family: passive; Index PN: 687; Lead Style: SMT; MFG: Panasonic; Material: chip; P/D_NUM: ERJ-2GE0R00X; Part Number: ERJ-2GE0R00X; Part Specific: RES 0.0 OHM 1/16W 0402 SMD; Power: 1/16W; Type: resistor; VPC: 1/16W; Vendor: Panasonic
R404 R406 R408 = PAS,R,large: DigiKey: P10.0KLCT-ND; DigiReel: P10.0KLDKR-ND; Family: passive; Index PN: 680; Lead Style: SMT; MFG: Panasonic; Material: chip; P/D_NUM: ERJ-2RKF1002X; Part Number: ERJ-2RKF1002X; Part Specific: RES 10K OHM 1/10W 1% 0402 SMD; Power: 1/16W; TOLERANCE: 1%; Type: resistor; VPC: 1/16W; Vendor: Panasonic
R407 = PAS,R,large: DNI: DNI; DigiKey: P10.0KLCT-ND; DigiReel: P10.0KLDKR-ND; Family: passive; Index PN: 680; Lead Style: SMT; MFG: Panasonic; Material: chip; P/D_NUM: ERJ-2RKF1002X; Part Number: ERJ-2RKF1002X; Part Specific: RES 10K OHM 1/10W 1% 0402 SMD; Power: 1/16W; TOLERANCE: 1%; Type: resistor; VENDOR: Panasonic; VPC: 1/16W
R635 = R_v4
R758 R759 = R_v4_1: DNI: DNI
R760 = R_v4_2: DNI: DNI
TP15-TP18 TP29 TP30 TP33 TP35 TP36 TP38-TP40 TP49-TP59 TP70-TP73 = T_POINT_R: Desc: TEST POINT, T/H, BLACK; Dist: Digi-Key; Dist p/n: 5001K-ND; Mfr: Keystone Electronics; Mfr p/n: 5001
TP145-TP148 TP200-TP207 TP261-TP265 = EM,TESTPOINT: Install: DNI; MFG: -- NOT A PART --; Part Specific: TP_20RD10; Type: testpoint via; Vendor: -- NOT A PART --
U15 = TMP_0: DigiKey: 296-18256-1-ND; DigiReel: 296-18256-6-ND; Family: logic; Index PN: 1027; Install: Y; Lead Style: SMT; MFG: Texas Instruments; P/D_NUM: SN74AUP1G07DCKR; Part Number: SN74AUP1G07DCKR; Part Specific: IC BUFF/DVR LOW PWR N-INV SC705, open drain; Type: buffer
U16 = CDCLVC1102_6: DigiKey: 296-27610-1-ND; DigiReel: 296-27610-6-ND; Family: logic; Install: Y; Lead Style: SMT; MFG: Texas Instruments; P/D_NUM: CDCLVC1102PWR; Part Number: CDCLVC1102PWR; Part Specific: IC CLK BUFFER 1:2 250MHZ 8TSSOP; Pin Cnt: 8; Type: buffer; VENDOR: Texas Instruments
U18 = CDCLVC1102_5: DigiKey: 296-27610-1-ND; DigiReel: 296-27610-6-ND; Family: logic; Install: Y; Lead Style: SMT; MFG: Texas Instruments; P/D_NUM: CDCLVC1102PWR; Part Number: CDCLVC1102PWR; Part Specific: IC CLK BUFFER 1:2 250MHZ 8TSSOP; Pin Cnt: 8; Type: buffer; VENDOR: Texas Instruments
U27 = LOG,XCVR,SN74AVC4T245RSV,2_1: DigiKey: 296-24366-1-ND; DigiReel: 296-24366-6-ND; Family: logic; Index PN: 942; Install: Y; Lead Style: SMT; MFG: Texas Instruments; P/D_NUM: SN74AVC4T245RSVR; Part Number: SN74AVC4T245RSVR; Part Specific: IC BUS TRANSCVR 4BIT 16-UQFN; Type: transceiver
U28 = TMP_111600: DNI: DNI; DigiKey: 296-32255-1-ND; DigiReel: 296-32255-6-ND; Family: logic; Index PN: 1026; Lead Style: SMT; MFG: Texas Instruments; P/D_NUM: 74LVC1G07; Part Number: SN74AUP1G06DCKT; Part Specific: IC INVERTER SINGLE 1INPUT SC705, Open Drain; Type: buffer
X3 = ANA,OSC,4P,2X: Family: analog; Index PN: 1151; Install: Y; Lead Style: SMT; MFG: ECS; P/D_NUM: Osc_24MHz; Part Number: ECS-2018-240-BN; Part Specific: OSC 24.000 MHZ 1.8V SMD; Type: oscillator; Vendor: ECS
U39 = TIDLP,DPP3438_6: DigiKey: ---; DigiReel: ---; Family: processor; Index PN: 1176; Lead Style: SMT; MFG: Texas Instruments; P/D_NUM: 2512737-0092; Package: Master; Part Number: 2512737-0092; Part Specific: IC, DPP3439 ASIC, DLP-PICO PROCESSOR; Type: dlp; Vendor: Texas Instruments; Install: Y
U40 = TIDLP,DPP3438_6: DigiKey: ---; DigiReel: ---; Family: processor; Index PN: 1176; Lead Style: SMT; MFG: Texas Instruments; P/D_NUM: 2512737-0092; Package: Slave; Part Number: 2512737-0092; Part Specific: IC, DPP3439 ASIC, DLP-PICO PROCESSOR; Type: dlp; Vendor: Texas Instruments; Install: Y
C262 = CAP_NP_13: ID: 114026; device: C0603
C263 = CAP_NP_8
C264 = 35SVPD22M: 1st Part Field: 50V; 2nd Part Field: OPT; 5th Part Field: 50ME270WX
C266 = CAP_NP_11: ICA_MFR_NAME: PANASONIC; ICA_PARTNUM: $$2075017$$ECJ1VB1E104K
C268 = CAP_NP_6
C269 = CAP_NP_4
C270 = CAP_NP_3
C271 = CAP_NP_1
C272 = CAP_NP_5
C275 = CAP_0.1uF_0603_6: Ceramic CAP X7R 6.3V 0.1uF; DNI: DNI
C410 = CAP_NP_16: ID: 114026; device: C0603
C411 = CAP_NP_7: ID: 114026; device: C0603
C412 = CAP_NP_2: ID: 114026; device: C0805
C413 = CAP_NP_15: ID: 114026; device: C0805
C414 = CAP_NP_12
C415 = CAP_NP_14
C416 = CAP_NP_9
C417 = CAP_NP
C418 = CAP_NP_10
C419 = CAP_NP_17
C420 = CAP_0.1uF_0603_3: Ceramic CAP X7R 6.3V 0.1uF
C424 = CAP_0.1uF_0603_4: Ceramic CAP X7R 6.3V 0.1uF
C384 C425 = CAP_0.1uF_0603_2: Ceramic CAP X7R 6.3V 0.1uF
C426 = CAP_0.1uF_0603_7: Ceramic CAP X7R 6.3V 0.1uF; DNI: DNI
C427 = CAP_0.1uF_0603_5: Ceramic CAP X7R 6.3V 0.1uF
D68 D69 = DIODE_SCHOTTKY: Diode, Schottky; MFG: STMICRO; Part Number: STPS0560Z; RATING: 60V, 500mA; SOURCE: DIGI 497-3787-1-ND
FB30 = FB_2: ID: 159352; device: R0603
FB20 FB31 = FB: ID: 159352; device: R0603
FB32 = FB_4: ID: 159352; device: R0603
FB33 = FB_3: ID: 159352; device: R0603
J28 = PJ1-022-SMT(0_9.65MM)
J32 J33 J43 = EM,HDR,2P,1R_2: DigiKey: 455-1611-ND; DigiReel: ---; Family: electro/mechanical; Lead Style: SMT; MFG: JST; P/D_NUM: B2B-EH-A(LF)(SN); Package: HDR_EH_A_2; Part Number: B2B-EH-A(LF)(SN); Part Specific: CONN HEADER EH TOP 2POS 2.5MM; Pin Cnt: 2; Pin Spacing: 2.5mm; Row Cnt: 1; Type: header; Vendor: JST
L10 = FB_1: ID: 56140
L11 = LPS3015-222ML(2_0.2u)
Q20 Q21 = BCP68_SOT_0: NPN Transistor; MFG: ON Semi; Part Number: BCP68T1G; SOURCE: DIGI BCP68T1GOSCT-ND
Q22 Q23 = 2N2222A: Transistor, Darlington NPN; MFG: DIODES; Part Number: MMBT6427-7-F; RATING: 40V, 500mA; SOURCE: DIGI MMBT6427-FDICT-ND
R472 = R_8
R479 R729 = RESISTOR
R480 = R_1: Part Description: RESISTOR 10K OHMS 1/10W 5% 0603; Part Type: 5%\0603; Sierra Part#: 1200100-103; Tolerance: 5%
R482 = R_14: Part Description: RESISTOR 10K OHMS 1/10W 5% 0603; Part Type: 5%\0603; Sierra Part#: 1200100-103; Tolerance: 5%
R483 = R_7: DNI: DNI; Part Description: RESISTOR 10K OHMS 1/10W 5% 0603; Part Type: 5%\0603; Sierra Part#: 1200100-103; Tolerance: 5%
R743 = R_5: Resistor, 5%, 1/10W; Part #: 101370-2201R
R744 = R_9: Resistor, 5%, 1/10W; Part #: 101370-2201R
R745 = R_18: Resistor, 5%, 1/10W; Part #: 101370-2201R
R749 = R_12: Part Description: RESISTOR 10K OHMS 1/10W 5% 0603; Part Type: 5%\0603; Sierra Part#: 1200100-103; Tolerance: 5%
R750 = R_6: DNI: DNI
R761 = R_3: ROHS CHIP RES  1/16W 150K 5% SMT 0402; P/N: 01.00036G503
R762 = R_2: ROHS CHIP RES  1/16W 150K 5% SMT 0402; P/N: 01.00036G503
R763 = R: ROHS CHIP RES  1/16W 150K 5% SMT 0402; P/N: 01.00036G503
R764 = R_17: ROHS CHIP RES  1/16W 150K 5% SMT 0402; DNI: DNI; P/N: 01.00036G503
R765 = R_4: ROHS CHIP RES  1/16W 150K 5% SMT 0402; P/N: 01.00036G503
R766 = R_13: ROHS CHIP RES  1/16W 150K 5% SMT 0402; DNI: DNI; P/N: 01.00036G503
R767 = R_11: ROHS CHIP RES  1/16W 150K 5% SMT 0402; P/N: 01.00036G503
R768 = R_10: ROHS CHIP RES  1/16W 150K 5% SMT 0402; P/N: 01.00036G503
R769 = R_16: ROHS CHIP RES  1/16W 150K 5% SMT 0402; P/N: 01.00036G503
R770 = R_15: ROHS CHIP RES  1/16W 150K 5% SMT 0402; P/N: 01.00036G503
R793 R795 R797 R798 = RESISTOR_H_TOL_1: P/D_NUM: MCR006YZPF1000; TOLERANCE: 1%; VENDOR: Rohm; VPC: ?
R794 R796 R799 = RESISTOR_H_TOL_1: DNI: DNI; P/D_NUM: MCR006YZPF1000; TOLERANCE: 1%; VENDOR: Rohm; VPC: ?
SW28 = SW_MAG-SPDT_0
TP212-TP222 TP224-TP231 TP245 = EM,TERM,TESTPOINT: DigiKey: ---; DigiReel: ---; Family: board feature; Index PN: 995; Install: DNI; MFG: -- NOT A PART --; Type: hole,plated; Vendor: -- NOT A PART --
U32 = RT8272_SOP8_7
U33 = RT8010-D_WDFN_3
U62 = 2.5VTO1_1.8V: ID: 136117; device: SOT223
U64 = TPS3808_1: IC VOLT SUPERVISOR 3.3V SOT23-6; DNI: DNI; Digikey Part Number: 296-17195-1-ND; Manuf Part Number: TPS3808G33DBVR; Manufacturer: Texas Instruments
U65 = SN74AHC1G08_2: IC, 2-Input AND Gate; MFG: TI; Part Number: SN74AHC1G08DCKR; SOURCE: PROVIDED BY TI
C385 = CAP_0.1uF_0603_1: Ceramic CAP X7R 6.3V 0.1uF; DNI: DNI
C391 = PAS,CAP,NP,large: DigiKey: 445-4991-1-ND; DigiReel: 445-4991-6-ND; Family: passive; Index PN: 916; Lead Style: SMT; MFG: TDK; Material: x5r; P/D_NUM: C1005X5R1A105M; Part Number: C1005X5R1A105M; Part Specific: CAP CER 1.0UF 10V X5R 0402; TOLERANCE: 20%; Type: capacitor; VENDOR: TDK; VPC: 10V
FB21 = FB_1: DNI: DNI; ID: 159352; device: R0603
J47 = CON5_1
L21 = INDUCTOR_IRON_7
R651 R652 R657 R659 R661 R662 R665-R667 R670 R671 R677 R679 R680 R685 = PAS,R,large: DigiKey: P10.0KLCT-ND; DigiReel: P10.0KLDKR-ND; Family: passive; Index PN: 680; Lead Style: SMT; MFG: Panasonic; Material: chip; P/D_NUM: ERJ-2RKF1002X; Part Number: ERJ-2RKF1002X; Power: 1/16W; TOLERANCE: 1%; Type: resistor; VENDOR: Panasonic; VPC: 1/16W
R653 = PAS,R,large: DNI: DNI; Family: passive; Index PN: 712; Lead Style: SMT; MFG: Panasonic; Material: chip; P/D_NUM: ERJ-2RKF1003X; Part Number: ERJ-2RKF1003X; Part Specific: RES 100K OHM 1/10W 1% 0402 SMD; Power: 1/16W; TOLERANCE: 1%; Type: resistor; VENDOR: Panasonic; VPC: 1/16W
R658 R660 R686 R690 R692 R776 R777 = PAS,R,large: DNI: DNI; DigiKey: P100LCT-ND; DigiReel: P100LDKR-ND; Family: passive; Index PN: 690; Lead Style: SMT; MFG: Panasonic; Material: chip; P/D_NUM: ERJ-2RKF1000X; Part Number: ERJ-2RKF1000X; Part Specific: RES 100 OHM 1/10W 1% 0402 SMD; Power: 1/16W; TOLERANCE: 1%; Type: resistor; VENDOR: Panasonic; VPC: 1/16W
R668 = 10K_OHM_1_10W_5%_0402
R757 = R_v4: DNI: DNI
U44 = TXS0102: DigiKey: 296-21931-1-ND; DigiReel: 296-21931-6-ND; Family: interface; Index PN: 877; Install: Y; Lead Style: SMT; MFG: Texas Instruments; P/D_NUM: TXS0102DCU; Part Number: TXS0102DCU; Part Specific: IC VOLT-LEVEL TRANSLATOR 8-US8; Type: driver; VENDOR: Texas Instruments
U45 U46 = LOG,XCVR,74x4T774: DigiKey: 296-24739-1-ND; DigiReel: 296-24739-6-ND; Family: logic; Index PN: 871; Lead Style: SMT; MFG: Texas Instruments; Part Specific: IC BUS TRANSCVR 4BIT DL 16TSSOP; Type: transceiver; Vendor: Texas Instruments
U47 = TPS71518DCK_4
U48 = INF,USB2SERIAL,CY7C65215: DigiKey: CY7C65215-32LTXI-ND; DigiReel: ---; Family: interface; Index PN: 1217; Lead Style: SMT; MFG: Cypress; Part Specific: IC USB TO UART BRIDGE DUAL 32QFN; Type: usb; Vendor: Cypress
U49 = LOG,INV,OPENDRN,SN74AUP1G06DCK: DigiKey: 296-17562-1-ND; DigiReel: 296-17562-6-ND; Family: logic; Index PN: 1026; Lead Style: SMT; MFG: Texas Instruments; Part Number: SN74AUP1G06DCKR; Part Specific: IC INVERTER SINGLE 1INPUT SC705, open drain; Type: buffer

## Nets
DGND: C6.2(N) C11.1(P) C12.1(P) C13.2(N) C14.2(N) C49.2(N) C75.2 C79.2 C146.2 C226.2(N) C227.2(N) C228.2 C229.1 C263.1 C264.2 C266.1 C268.1 C269.1 C270.1 C271.2 C272.2 C273.2 C274.2 C368.2(N) C369.2(N) C378.2(N) C379.2(N) C380.2(N) C381.2(N) C382.2(N) C383.2(N) C384.1 C385.2 C386.2 C387.2(N) C388.2(N) C389.2(N) C390.2(N) C391.2(N) C392.2(N) C393.2(N) C410.1 C411.1 C412.2 C413.2 C414.1 C415.1 C416.1 C417.1 C418.1 C419.1 C420.2 C423.1 C424.1 C425.2 C426.2 C427.2 D25.2(ANODE) D26.2(ANODE) D68.2(A) D69.2(A) ED13.2(ANODE) ED14.2(ANODE) ED15.2(ANODE) ED16.2(ANODE) ED19.2(ANODE) ED21.2(ANODE) ED22.2(ANODE) ED36.2(ANODE) ED37.2(ANODE) J11.3 J21.6 J28.3 J28.4 J28.5 J32.3 J33.3 J43.3 J47.5(GND) J47.6(GND) J47.7(GND) J47.8(GND) J47.9(GND) Q22.1(EMITTER) Q23.1(EMITTER) R63.1 R64.1 R108.2 R127.2 R129.2 R144.2 R183.1 R185.1 R206.1 R207.1 R392.2(N2) R393.1(N1) R401.1(N1) R407.1(N1) R474.1 R479.1 R482.2 R483.2 R656.1(N1) R662.2(N2) R669.1(N1) R671.2(N2) R681.1(N1) R685.1(N1) R745.2 R749.2 R797.1(N1) SW28.4 SW28.5 U11.4(GND) U15.3(GND) U16.4(GND) U18.4(GND) U25.3(GND) U26.3(GND) U27.8(GND) U28.3(GND) U32.4(GND) U32.9(EP) U33.2(GND) U36.3(GND) U37.3(GND) U39.C10(HWTEST_EN) U40.C10(HWTEST_EN) U44.2(GND) U45.10(GND) U46.10(GND) U47.2(GND) U48.4(VSSD) U48.17(VSSD) U48.20(VSSD) U48.24(VSSA) U49.3(GND) U50.3(GND) U51.3(GND) U62.2(GND1) U62.4(GND2) U64.5(GND) U64.7(PPAD) U65.3 X3.2(GND) ; also on sheet 1 2 5 6 11 12
P5V: C272.1 FB31.2 R477.2 R740.1 TP245.1(P1) U33.4(Vin) ; also on sheet 2 6 11 12
P12V: C414.2 C415.2 FB30.1 Q20.2(C) Q20.4(C) Q21.2(C) Q21.4(C) R472.2 R622.2 R761.1 R762.1 R764.1 R766.1 TP146.1(P1)
VIN: C263.2 C264.1 C410.2 R471.2 R750.2 R793.2(N2) SW28.2 TP148.1(P1) U32.2(Vin) ; also on sheet 12
VINTF: C379.1(P) R1.2 R2.2 R9.2 U44.3(VCCA) ; also on sheet 1
3DR: R144.1 U39.N6(3DR) U40.N6(3DR) ; also on sheet 6
ADP_PWR: J28.1 R750.1 SW28.3
CY_GPIO_0: R692.2(N2) U48.25(GPIO_0) U51.2(A)
CY_GPIO_1: R690.2(N2) U48.26(GPIO_1) U50.2(A)
CY_GPIO_2: TP231.1(P1) U48.27(SCB0_1/GPIO_2)
CY_GPIO_7: R685.2(N2) R686.2(N2) U48.32(GPIO_7) U49.2(A)
CY_GPIO_8: R678.2(N2) U48.2(SCB0_0/GPIO_8)
CY_GPIO_10: R673.2(N2) U48.5(SCB1_0/GPIO_10)
CY_GPIO_11: R672.2(N2) U48.6(SCB1_1/GPIO_11)
CY_GPIO_12: R668.2 R675.2(N2) U48.7(SCB1_2/GPIO_12)
CY_GPIO_13: R674.2(N2) U48.8(SCB1_3/GPIO_13)
CY_GPIO_15: R683.1(N1) U48.10(SCB1_5/GPIO_15)
CY_GPIO_16: R684.1(N1) U48.13(GPIO_16)
CY_GPIO_17: R758.2 U48.21(GPIO_17)
CY_GPIO_18: R757.2 U48.22(GPIO_18)
CY_I2C_SCL: R664.2(N2) U48.28(SCB0_2/GPIO_3)
CY_I2C_SDA: R663.2(N2) U48.29(SCB0_3/GPIO_4)
CY_IIC0_SCL: R654.2(N2) R658.1(N1) R776.2(N2) TP212.1(P1) U44.5(A1)
CY_IIC0_SDA: R655.2(N2) R660.1(N1) R777.2(N2) TP213.1(P1) U44.4(A2)
CY_IIC_OE: R653.1(N1) R656.2(N2) TP214.1(P1) U44.6(OE) U48.3(SCB0_5/GPIO_9)
CY_P3P3V: C378.1(P) C387.1(P) C388.1(P) C390.1(P) C392.1(P) C393.1(P) D66.1(ANODE) D67.1(ANODE) FB20.1 FB21.1 R651.2(N2) R652.2(N2) R653.2(N2) R668.1 U44.7(VCCB) U48.1(VDDD) U48.23(VDDD) U49.5(PWR) U50.5(PWR) U51.5(PWR)
CY_VBUS: C389.1(P) J47.1(VUSB) R676.2(N2) U48.19(VBUS)
CY_VCCD: C391.1(P) U48.16(VCCD)
DATEN_CMD: U39.P2(DATEN_CMD) U40.P2(DATEN_CMD) ; also on sheet 6
DPP_P1P8V: C368.1(P) C423.2 R107.2 R128.2 R169.2 R172.1 R179.1 R209.1 R210.1 R390.1(N1) U15.5(PWR) U36.5(PWR) ; also on sheet 1 5 6 11 12
DPP_SPICLK: R182.2 U39.A13(SPI0_CLK)
DPP_SPICSZ0: R186.2 U39.A14(SPI0_CSZ0)
DPP_SPICSZ1: R344.2 U39.C12(SPI0_CSZ1)
DPP_SPIDOUT: R184.2 U39.B13(SPI0_DOUT)
E_SCL: D25.1(CATHODE) J11.2 Q4.3(DRAIN) R176.1 R221.1 TP203.1(P1)
E_SDA: D26.1(CATHODE) J11.1 Q7.3(DRAIN) R6.1 R220.1 TP202.1(P1)
EXT_CLK: ED16.1(CATHODE) J21.4 U27.12(4A)
EXT_CSZ: ED13.1(CATHODE) J21.1 R635.2 U27.4(1A)
EXT_DI-FLASH_DO: ED15.1(CATHODE) J21.3 R401.2(N2) U27.9(3A)
EXT_DO-FLASH_DI: ED14.1(CATHODE) J21.2 U27.7(2A)
EXT_M_SPI_CLK: R388.1 ; also on sheet 5
EXT_M_SPI_CSZ: J29.1 R386.1 R618.2 ; also on sheet 5
EXT_M_SPI_DIN: R387.1 ; also on sheet 5
EXT_M_SPI_DOUT: R389.1 ; also on sheet 5
EXT_S_SPI_CLK: R411.1 ; also on sheet 5
EXT_S_SPI_CSZ: J30.1 R409.1 R620.2 ; also on sheet 5
EXT_S_SPI_DIN: R410.1 ; also on sheet 5
EXT_S_SPI_DOUT: R412.1 ; also on sheet 5
F1_P: D68.1(C) FB32.2 Q20.3(E)
F2_P: D69.1(C) FB33.2 Q21.3(E)
Fan1_Lock: ED36.1(CATHODE) J32.2 R763.2 ; also on sheet 2
FAN1_PWM: R769.2 ; also on sheet 2
FAN1_PWR: C416.2 C417.2 FB32.1 J32.1 R764.2
Fan2_Lock: ED37.1(CATHODE) J33.2 R765.2 ; also on sheet 2
FAN2_PWM: R770.2 ; also on sheet 2
FAN2_PWR: C418.2 C419.2 FB33.1 J33.1 R766.2
HSYNC_CS: U39.N5(HSYNC_CS) U40.N5(HSYNC_CS) ; also on sheet 6
IIC0_SCL: R177.1 R654.1(N1) TP201.1(P1) U39.N10(IIC0_SCL) ; also on sheet 2 6
IIC0_SDA: R178.1 R655.1(N1) TP200.1(P1) U39.N9(IIC0_SDA) ; also on sheet 2 6
IIC1_SCL: R1.1 R3.1 U39.R11(IIC1_SCL) U40.N10(IIC0_SCL)
IIC1_SDA: R2.1 R4.1 U39.R10(IIC1_SDA) U40.N9(IIC0_SDA)
INT_M_SPI_CSZ: J29.3 R345.2 R386.2 R619.1 U18.1(\\~{C}S)
INT_S_SPI0_CSZ0: J30.3 R60.2 R409.2 R621.1 U16.1(\\~{C}S)
JTAG_TCK: TP72.1(TP) U40.P12(JTAGTCK)
JTAG_TCK_M: TP70.1(TP) U39.P12(JTAGTCK)
JTAG_TDI: TP38.1(TP) U40.P13(JTAGTDI)
JTAG_TDI_M: TP16.1(TP) U39.P13(JTAGTDI)
JTAG_TDO: TP29.1(TP) U40.N13(JTAGTDO1)
JTAG_TDO2: R210.2 U40.N12(JTAGTDO2)
JTAG_TDO2_M: R209.2 U39.N12(JTAGTDO2)
JTAG_TDO_M: TP15.1(TP) U39.N13(JTAGTDO1)
JTAG_TMS: TP39.1(TP) U40.M13(JTAGTMS1)
JTAG_TMS2: TP73.1(TP) U40.N11(JTAGTMS2)
JTAG_TMS2_M: TP71.1(TP) U39.N11(JTAGTMS2)
JTAG_TMS_M: TP17.1(TP) U39.M13(JTAGTMS1)
JTAG_TRSTZ: R207.2 TP40.1(TP) U40.P11(JTAGTRSTZ)
JTAG_TRSTZ_M: R206.2 TP18.1(TP) U39.P11(JTAGTRSTZ)
M_CLK: R402.2(N2) U27.14(4B1)
M_CSZ: R395.2(N2) U27.2(1B1)
M_EXT_DI: R400.2(N2) U27.11(3B1)
M_EXT_DO: R397.2(N2) U27.5(2B1)
M_HOST_IRQ: R128.1 R129.1 R149.1 R683.2(N2) TP222.1(P1) U25.2(A) U39.N8(HOST_IRQ) ; also on sheet 2
M_OSC_OUT: R12.2 U39.H1(PLL_REFCLK_I) U40.H1(PLL_REFCLK_I)
M_OSC_OUT_T: R12.1 X3.3(OUT)
M_VOSC: C6.1(P) R9.1 X3.1(EN) X3.4(VDD)
MCU_ACK: R687.1(N1) TP225.1(P1) ; also on sheet 2
MCU_DPP_RST: R404.1(N1) R407.2(N2) TP206.1(P1) U28.2(A) ; also on sheet 2
MCU_P3.2: R758.1 ; also on sheet 2
MCU_P3.3: R757.1 ; also on sheet 2
MCU_REQ: R688.1(N1) TP226.1(P1) ; also on sheet 2
MCU_SW_ONOFF: R686.1(N1) R729.2 TP224.1(P1) U49.4(Y) ; also on sheet 2
MSP430_ACK: R687.2(N2) U48.31(GPIO_6)
MSP430_REQ: R688.2(N2) U48.30(SCB0_4/GPIO_5)
MSP430_S_SCL: R487.2 R776.1(N1) ; also on sheet 2
MSP430_S_SDA: R488.2 R777.1(N1) ; also on sheet 2
MSP_PROJ_ON: R798.2(N2) ; also on sheet 2
P3P3V: C75.1 C226.1(P) C227.1(P) C229.2 C369.1(P) C424.2 C427.1 D33.1(ANODE) D34.1(ANODE) D43.1(ANODE) D56.1(ANODE) D57.1(ANODE) FB20.2 L9.2 Q4.1(GATE) Q7.1(GATE) R3.2 R4.2 R149.2 R162.2 R171.1 R173.2 R175.2 R382.2 R384.2 R478.1 R657.2(N2) R661.2(N2) R665.2(N2) R666.2(N2) R667.2(N2) R670.2(N2) R677.2(N2) R679.2(N2) R680.2(N2) R729.1 R763.1 R765.1 R794.2(N2) R795.2(N2) TP147.1(P1) U25.5(PWR) U26.5(PWR) U28.5(PWR) U37.5(PWR) U64.1(VDD) U65.5 ; also on sheet 1 2 6 11 12
P3P3V_PWR_EN: R481.2 TP145.1(P1) ; also on sheet 2
P3P3V_T: C380.1(P) C382.1(P) R657.1(N1) U45.16(VCCA) U46.16(VCCA)
PAD_RESETZ: R169.1 U15.2(A) ; also on sheet 12
PARKZ: R179.2 R615.2(N2) U39.C13(PARKZ) U40.C13(PARKZ) ; also on sheet 12
PCLK: C12.2(N) C13.1(P) R197.2 R198.2 U11.1(CLKIN) ; also on sheet 6
PCLK_M: C11.2(N) R197.1 U11.8(Y1) U39.P3(PCLK)
PCLK_S: C14.1(P) R198.1 U11.3(Y0) U40.P3(PCLK)
PCLK_VDD: C49.1(P) L9.1 U11.2(1G) U11.6(VDD)
PDATA0: U39.K2(PDATA_0) U40.K2(PDATA_0) ; also on sheet 6
PDATA1: U39.K1(PDATA_1) U40.K1(PDATA_1) ; also on sheet 6
PDATA2: U39.L2(PDATA_2) U40.L2(PDATA_2) ; also on sheet 6
PDATA3: U39.L1(PDATA_3) U40.L1(PDATA_3) ; also on sheet 6
PDATA4: U39.M2(PDATA_4) U40.M2(PDATA_4) ; also on sheet 6
PDATA5: U39.M1(PDATA_5) U40.M1(PDATA_5) ; also on sheet 6
PDATA6: U39.N2(PDATA_6) U40.N2(PDATA_6) ; also on sheet 6
PDATA7: U39.N1(PDATA_7) U40.N1(PDATA_7) ; also on sheet 6
PDATA16: U39.R6(PDATA_16) U40.R6(PDATA_16) ; also on sheet 6
PDATA17: U39.P7(PDATA_17) U40.P7(PDATA_17) ; also on sheet 6
PDATA18: U39.R7(PDATA_18) U40.R7(PDATA_18) ; also on sheet 6
PDATA19: U39.P8(PDATA_19) U40.P8(PDATA_19) ; also on sheet 6
PDATA20: U39.R8(PDATA_20) U40.R8(PDATA_20) ; also on sheet 6
PDATA21: U39.P9(PDATA_21) U40.P9(PDATA_21) ; also on sheet 6
PDATA22: U39.R9(PDATA_22) U40.R9(PDATA_22) ; also on sheet 6
PDATA23: U39.P10(PDATA_23) U40.P10(PDATA_23) ; also on sheet 6
PDATA_8: U39.R1(PDATA_8) U40.R1(PDATA_8) ; also on sheet 6
PDATA_9: U39.R2(PDATA_9) U40.R2(PDATA_9) ; also on sheet 6
PDATA_10: U39.R3(PDATA_10) U40.R3(PDATA_10) ; also on sheet 6
PDATA_11: U39.P4(PDATA_11) U40.P4(PDATA_11) ; also on sheet 6
PDATA_12: U39.R4(PDATA_12) U40.R4(PDATA_12) ; also on sheet 6
PDATA_13: U39.P5(PDATA_13) U40.P5(PDATA_13) ; also on sheet 6
PDATA_14: U39.R5(PDATA_14) U40.R5(PDATA_14) ; also on sheet 6
PDATA_15: U39.P6(PDATA_15) U40.P6(PDATA_15) ; also on sheet 6
PDM_CVS_TE: R127.1 U39.N4(PDM_CVS_TE) U40.N4(PDM_CVS_TE)
PRG_FLSH: ED19.1(CATHODE) J21.5 R404.2(N2) R408.2(N2) TP207.1(P1)
PROJ_ON: R799.1(N1) TP264.1(P1) U65.4(Y) ; also on sheet 11 12
RESETZ: R172.2 R394.2(N2) R406.1(N1) R408.1(N1) R614.2(N2) TP205.1(P1) U15.4(Y) U39.C11(RESETZ) U40.C11(RESETZ)
RREF: U39.F3(RREF) U40.F3(RREF)
S_CLK: R403.2(N2) U27.13(4B2)
S_CSZ: R396.2(N2) U27.3(1B2)
S_DPP_SPICLK: R67.2 U40.A13(SPI0_CLK)
S_DPP_SPICSZ0: R69.2 U40.A14(SPI0_CSZ0)
S_DPP_SPICSZ1: R71.2 U40.C12(SPI0_CSZ1)
S_DPP_SPIDOUT: R68.2 U40.B13(SPI0_DOUT)
S_EXT_DI: R399.2(N2) U27.10(3B2)
S_EXT_DO: R398.2(N2) U27.6(2B2)
S_HOST_IRQ: R107.1 R108.1 R162.1 R684.2(N2) TP221.1(P1) U26.2(A) U40.N8(HOST_IRQ) ; also on sheet 2
S_IIC1_SCL: R150.2 U40.R11(IIC1_SCL)
S_IIC1_SDA: R151.2 U40.R10(IIC1_SDA)
S_SPI0_CLK: R63.2 R67.1 R403.1(N1) R411.2 U16.6(CLK) U45.12(B3)
S_SPI0_CSZ0: J30.2 R69.1 R396.1(N1) R620.1 R621.2 U45.11(B4)
S_SPI0_CSZ1: R65.2 R71.1 TP57.1(TP)
S_SPI0_DIN: R64.2 R399.1(N1) R410.2 U16.2(DO) U40.B12(SPI0_DIN) U45.13(B2)
S_SPI0_DIR1: R661.1(N1) U45.1(DIR1)
S_SPI0_DIR2: R662.1(N1) U45.2(DIR2)
S_SPI0_DIR3: R665.1(N1) U45.7(DIR3)
S_SPI0_DIR4: R666.1(N1) U45.8(DIR4)
S_SPI0_DOUT: R68.1 R398.1(N1) R412.2 U16.5(DIN) U45.14(B1)
S_TSTPT_0: TP49.1(TP) U40.R12(TSTPT_0)
S_TSTPT_1: TP50.1(TP) U40.R13(TSTPT_1)
S_TSTPT_2: TP51.1(TP) U40.R14(TSTPT_2)
S_TSTPT_3: TP52.1(TP) U40.R15(TSTPT_3)
S_TSTPT_4: TP53.1(TP) U40.P14(TSTPT_4)
S_TSTPT_5: TP54.1(TP) U40.P15(TSTPT_5)
S_TSTPT_6: TP55.1(TP) U40.N14(TSTPT_6)
S_TSTPT_7: TP59.1(TP) U40.N15(TSTPT_7)
S_VFLSH: C146.1 C228.1 R60.1 R65.1 R612.2(N2) R635.1 R659.2(N2) U16.3(WP) U16.7(HOLD) U16.8(VCC) U27.16(VCC) ; also on sheet 1
SPI0_CLK: R182.1 R183.2 R388.2 R402.1(N1) U18.6(CLK) U46.12(B3)
SPI0_CSZ0: J29.2 R186.1 R395.1(N1) R618.1 R619.2 U46.11(B4)
SPI0_CSZ1: R189.2 R344.1 TP56.1(TP)
SPI0_DIN: R185.2 R387.2 R400.1(N1) U18.2(DO) U39.B12(SPI0_DIN) U46.13(B2)
SPI0_DIR1: R670.1(N1) U46.1(DIR1)
SPI0_DIR2: R671.1(N1) U46.2(DIR2)
SPI0_DIR3: R677.1(N1) U46.7(DIR3)
SPI0_DIR4: R679.1(N1) U46.8(DIR4)
SPI0_DOUT: R184.1 R389.2 R397.1(N1) U18.5(DIN) U46.14(B1)
SPI_BUS_SEL: J35.2 R393.2(N2) TP204.1(P1) U27.1(S) ; also on sheet 2
STAT_LED0: R691.2(N2) R692.1(N1) U51.4(Y)
STAT_LED1: R689.2(N2) R690.1(N1) U50.4(Y)
SUSPEND: TP227.1(P1) U48.11(SUSPEND)
SW_SYS_ON-OFF: R760.1 ; also on sheet 2
TRIG_OUT_A: R637.1 ; also on sheet 11
TRIG_OUT_B: R638.1 ; also on sheet 11
TSTPT_0: TP30.1(TP) U39.R12(TSTPT_0)
TSTPT_1: R637.2 R639.1 U39.R13(TSTPT_1)
TSTPT_2: R638.2 U39.R14(TSTPT_2)
TSTPT_3: TP33.1(TP) U39.R15(TSTPT_3)
TSTPT_4: R639.2 U39.P14(TSTPT_4)
TSTPT_5: TP35.1(TP) U39.P15(TSTPT_5)
TSTPT_6: TP36.1(TP) U39.N14(TSTPT_6)
TSTPT_7: TP58.1(TP) U39.N15(TSTPT_7)
USB_LDO_3.3V: C386.1 FB21.2 U47.5(OUT)
USB_SPI_CLK: R674.1(N1) TP218.1(P1) U45.5(A3) U46.5(A3)
USB_SPI_CSZ: R675.1(N1) TP219.1(P1) U45.6(A4) U46.6(A4)
USB_SPI_M_OEZ: R678.1(N1) R680.1(N1) R681.2(N2) TP220.1(P1) U46.9(~{OE})
USB_SPI_MISO: R673.1(N1) TP217.1(P1) U45.4(A2) U46.4(A2)
USB_SPI_MOSI: R672.1(N1) TP216.1(P1) U45.3(A1) U46.3(A1)
USB_SPI_S_OEZ: R667.1(N1) R669.2(N2) R682.2(N2) TP215.1(P1) U45.9(~{OE})
USBDM: L21.3 U48.15(USBDM)
USBDP: L21.2 U48.14(USBDP)
VFLSH: C79.1 R189.1 R345.1 U18.3(WP) U18.7(HOLD) U18.8(VCC) ; also on sheet 1 5
VFLSH_T: C381.1(P) C383.1(P) R659.1(N1) U45.15(VCCB) U46.15(VCCB)
VSENSE: R747.1 R749.1 U32.5(FB)
VSYNC_WE: U39.P1(VSYNC_WE) U40.P1(VSYNC_WE) ; also on sheet 6
WAKEUP: TP228.1(P1) U48.12(WAKEUP)
N27253941: R390.2(N2) R392.1(N1) R394.1(N1) U27.15(\\~{OE})
N27849955: Q7.2(SOURCE) R151.1 R175.1 R178.2 R220.2 R488.1
N27849973: Q4.2(SOURCE) R150.1 R173.1 R177.2 R221.2 R487.1
N27849989: R6.2 R171.2 R176.2 R740.2 R759.1
N28408056: D43.2(CATHODE) R479.2
N28408098: R477.1 R481.1 R483.1 U33.1(EN)
N28408247: C268.2 C269.2 C270.2 C271.1 L10.2 R472.1 R747.2
N28408400: C262.2 L10.1 U32.3(PH)
N28408404: R745.1 U32.8(RT)
N28408497: C266.2 R743.2 U32.6(COMP)
N28408620: C273.1 C274.1 C275.2 L11.2 R478.2 R480.1
N28408656: L11.1 U33.3(SW)
N28408705: C275.1 R480.2 R482.1 U33.5(FB)
N29431095: R382.1 R383.2(N2) U25.4(Y)
N29431100: D33.2(CATHODE) R383.1(N1)
N29462949: R384.1 R385.2(N2) U26.4(Y)
N29462963: D34.2(CATHODE) R385.1(N1)
N30993132: J35.1 R612.1(N1)
N31003375: R613.2(N2) U36.4(Y)
N31003387: D56.2(CATHODE) R613.1(N1)
N31003389: R614.1(N1) U36.2(A)
N31024435: R616.2(N2) U37.4(Y)
N31024437: D57.2(CATHODE) R616.1(N1)
N31024439: R615.1(N1) U37.2(A)
N33198426: R406.2(N2) U28.4(Y)
N36811782: C411.2 R744.2
N36816821: R743.1 R744.1
N37525033: J11.4 R759.2 R760.2
N37631809: Q22.3(COLLECTOR) R761.2 R767.2
N37631828: Q22.2(BASE) R769.1
N37631867: Q20.1(B) R767.1
N37687280: Q23.3(COLLECTOR) R762.2 R768.2
N37687290: Q23.2(BASE) R770.1
N37687329: Q21.1(B) R768.1
N40406231: J43.1 R622.1
N41611832: C262.1 U32.1(BOOT)
N42053668: C413.1 C420.1 FB31.1 U62.3(Vout)
N42053691: C412.1 FB30.2 U62.1(Vin)
N42058572: R795.1(N1) R796.1(N1) TP263.1(P1) U65.1(A)
N42058589: C425.1 R793.1(N1) R797.2(N2) TP261.1(P1) U64.2(SENSE)
N42058678: R798.1(N1) R799.2(N2) TP262.1(P1) U65.2(B)
N42058717: R796.2(N2) U64.6(\\~{RESE}T)
N42058739: C426.1 R794.1(N1) U64.3(CT)
N42058747: TP265.1(P1) U64.4(\\~{M}R)
N42194957: D67.2(CATHODE) R691.1(N1)
N42195125: C385.1 U47.4(NC)
N42195135: C384.2 R676.1(N1) U47.1(IN) U47.3(EN)
N42195800: R651.1(N1) R660.2(N2) R663.1(N1) TP229.1(P1) U44.1(B2)
N42195802: R652.1(N1) R658.2(N2) R664.1(N1) TP230.1(P1) U44.8(B1)
N42196165: ED21.1(CATHODE) J47.3(D+) L21.1
N42196187: ED22.1(CATHODE) J47.2(D-) L21.4
N42196497: D66.2(CATHODE) R689.1(N1)
N46081254: R471.1 R474.2 U32.7(EN)
N46697836: R682.1(N1) U48.9(SCB1_4/GPIO_14)

Not connected (* = marked no-connect by the designer): J28 2*; J43 2*; J47 4(ID)*; SW28 1*; U11 5(NC5)* 7(NC7)*; U39 C1(DD3P)* C2(DD3N)* D1(DD2P)* D2(DD2N)* E1(DCLKP)* E2(DCLKN)* F1(DD1P)* F2(DD1N)* G1(DD0P)* G2(DD0N)* J1(PLL_REFCLK_O)*; U40 C1(DD3P)* C2(DD3N)* D1(DD2P)* D2(DD2N)* E1(DCLKP)* E2(DCLKN)* F1(DD1P)* F2(DD1N)* G1(DD0P)* G2(DD0N)* J1(PLL_REFCLK_O)*; U48 18(nXRES)*

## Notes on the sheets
sheet 7
- -->MCU Slave I2C_SCL
- -->DLPC3439 I2C_SCL
- -->DLPC3439 I2C_SDA
- -->MCU Slave I2C_SDA
- DIR Pin:
  "L"= B to A
  "H" =A to B
- (CY_GPIO_9)
- -->DLPC3439 Slave SPI Flash
- (CY_GPIO_14)
- -->DLPC3439 Master SPI Flash
- (CY_GPIO_8)
- SCB1 configured:
  SPI Master (Mode 3)
- SCB0 configured :
  I2C Master (Mode 5)
- Mini USB type-B
sheet 8
- OD=6mm
  ID=2.5mm
- 3  2  1
- +19V
  Power
  Input
- SOIC8
- 5
- 3
- 2
- Vout=0.8V(1+R747/R749)
- 4
- 1
- Top view
- SOT23-5
- SC-70
- QFN-6
- Vit=0.405 V
- Vout=0.6V(1+R480/R482)
- C
- 4
- BCP68
- 1
- 2
- 3
- B  C  E
- C
  3
- 2
  B
- 1
  E
- Fan1
- Fan2
- Fan3
sheet 9
- SLAVE
- MASTER
- From IT6801
  HDMI Receiver
- (PDATA0/Blue_0)
- (PDATA1/Blue_1)
- (PDATA2/Blue_2)
- (PDATA3/Blue_3)
- (PDATA4/Blue_4)
- (PDATA5/Blue_5)
- (PDATA6/Blue_6)
- (PDATA7/Blue_7)
- (PDATA8/Green_0)
- (PDATA9/Green_1)
- (PDATA10/Green_2)
- (PDATA11/Green_3)
- (PDATA12/Green_4)
- (PDATA13/Green_5)
- (PDATA14/Green_6)
- (PDATA15/Green_7)
- (PDATA16/Red_0)
- (PDATA17/Red_1)
- (PDATA18/Red_2)
- (PDATA19/Red_3)
- (PDATA20/Red_4)
- (PDATA21/Red_5)
- (PDATA22/Red_6)
- (PDATA23/Red_7)
- MASTER
- SLAVE
- Clock buffer
- The DSI Port is not used.
  Inputs are left unconnected per ASIC spec recommendation.
sheet 10
- Slave SPI Flash
- Master SPI Flash
- SLAVE
- MASTER
- To Slave DLPC3439
- D
- 3
- OE="H" Disconnect
- S="L" A port = B1 port (Master)
  S="H" A port = B2 port(Slave)
- 2N7002
- 1       2
- G       S
- △
- G
- △
- S
- D
- ■
- △
- I2C Connector
- B1-->Master Flash
  B2-->Slave Flash
- G
- To Master DLPC3439 I2C
- S
- D
- To MSP430_Slave_I2C
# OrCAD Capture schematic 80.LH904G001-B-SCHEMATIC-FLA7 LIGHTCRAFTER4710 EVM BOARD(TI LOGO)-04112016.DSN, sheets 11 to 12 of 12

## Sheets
11 P06: DLPC3439_GPIO,LED_SEL,TRIG: size D
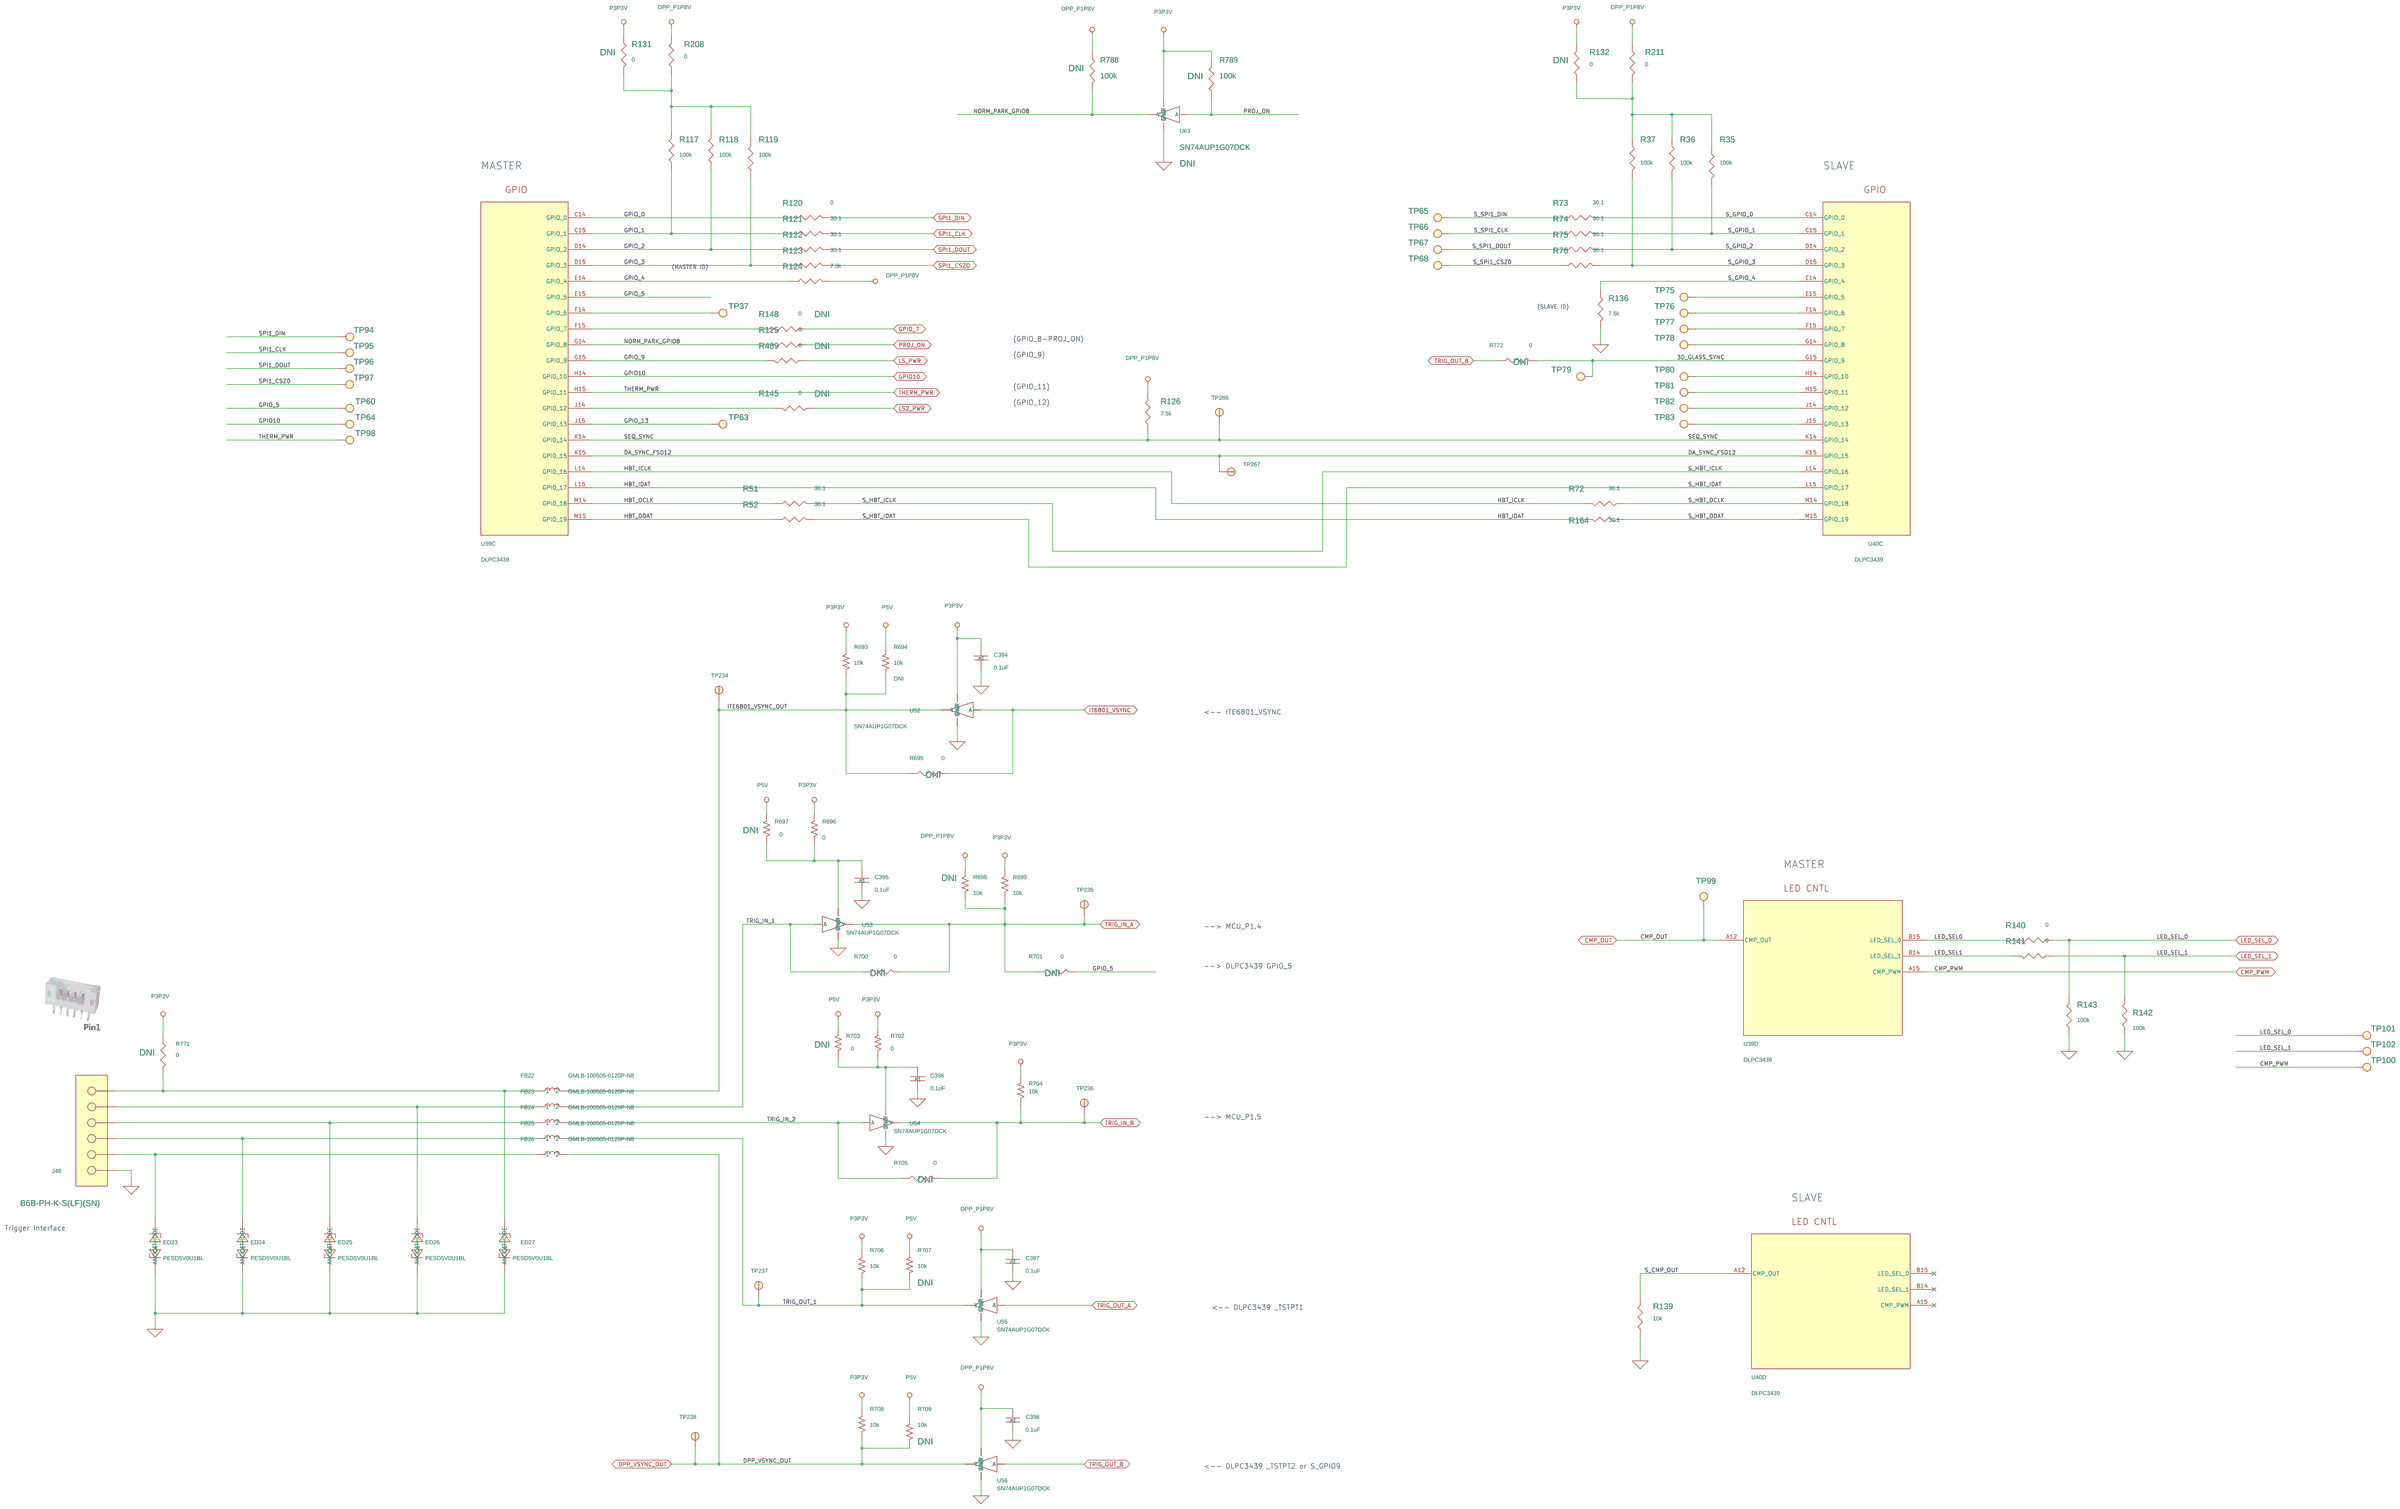
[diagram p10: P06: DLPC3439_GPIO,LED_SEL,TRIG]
12 P10: DLPA3005_PMIC & LED Driver: size D

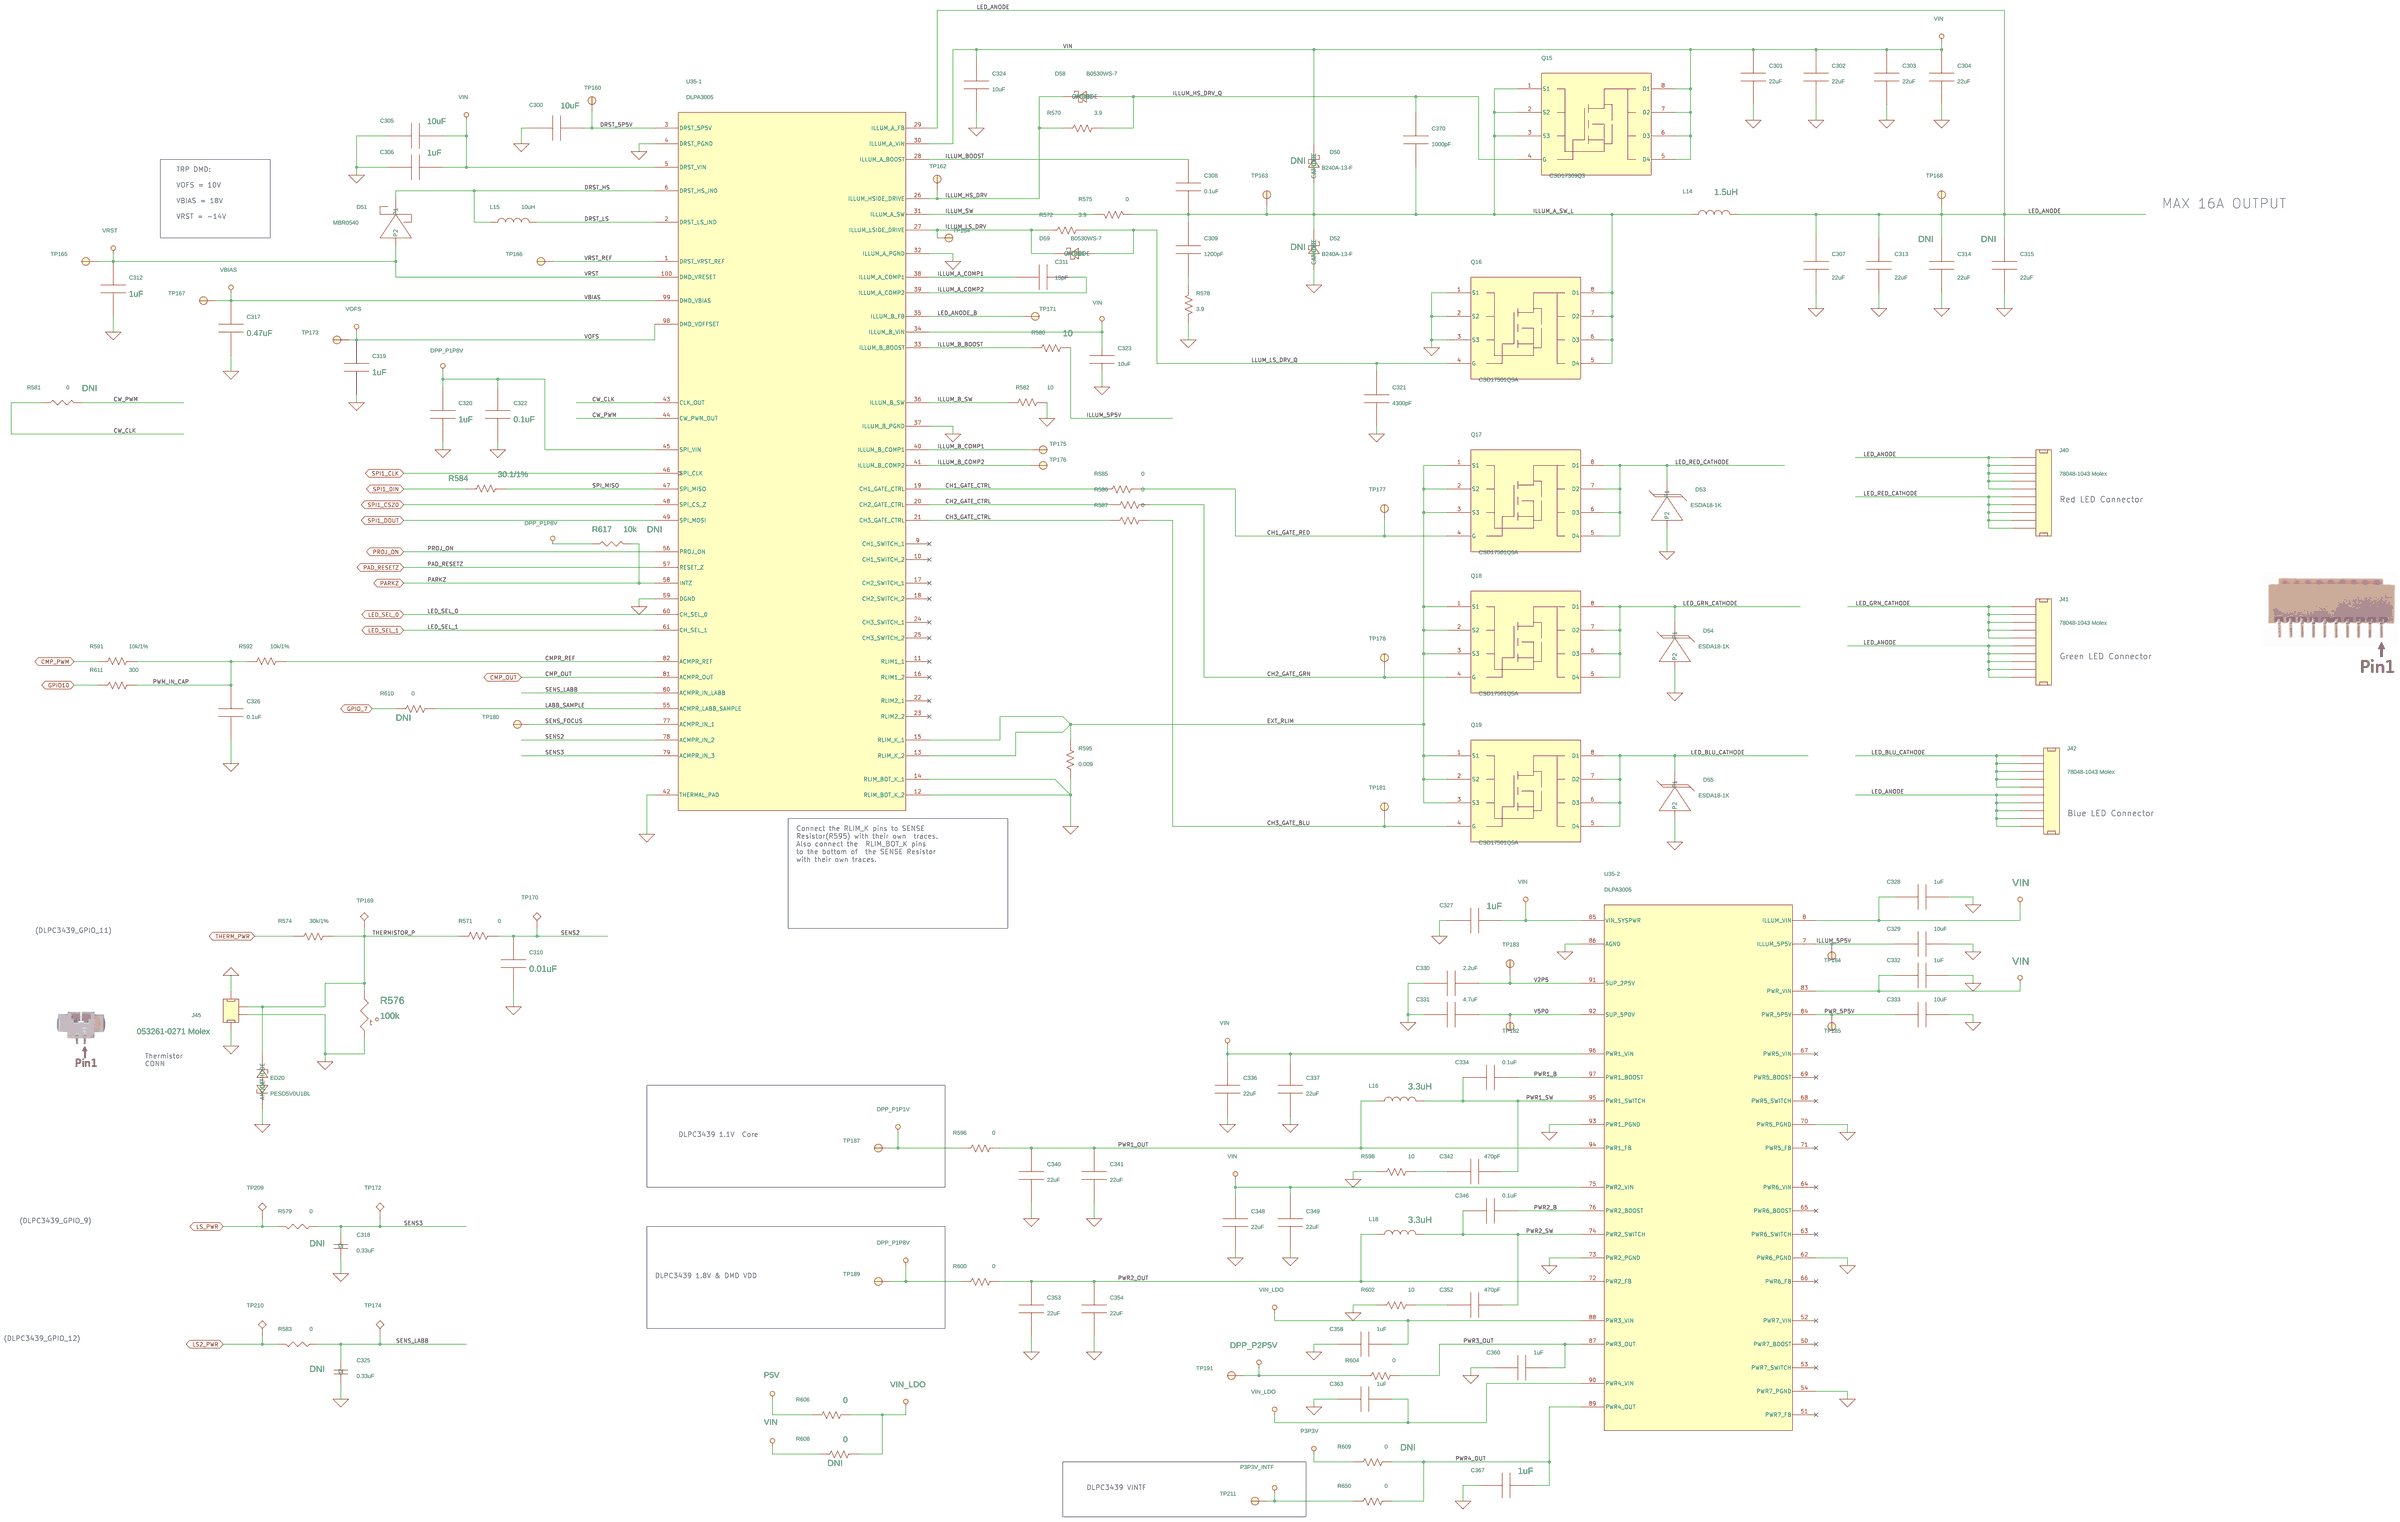
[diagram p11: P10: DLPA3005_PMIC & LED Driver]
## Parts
sheet P06: DLPC3439_GPIO,LED_SEL,TRIG
C394  0.1uF  [C0402\H0.55]
C395  0.1uF  [C0402\H0.55]
C396  0.1uF  [C0402\H0.55]
C397  0.1uF  [C0402\H0.55]
C398  0.1uF  [C0402\H0.55]
ED23  PESD5V0U1BL  [SOD882\2A1C\H0.5]
ED24  PESD5V0U1BL  [SOD882\2A1C\H0.5]
ED25  PESD5V0U1BL  [SOD882\2A1C\H0.5]
ED26  PESD5V0U1BL  [SOD882\2A1C\H0.5]
ED27  PESD5V0U1BL  [SOD882\2A1C\H0.5]
FB22  GMLB-100505-0120P-N8  [L0402\H0.6]
FB23  GMLB-100505-0120P-N8  [L0402\H0.6]
FB24  GMLB-100505-0120P-N8  [L0402\H0.6]
FB25  GMLB-100505-0120P-N8  [L0402\H0.6]
FB26  GMLB-100505-0120P-N8  [L0402\H0.6]
J48  B6B-PH-K-S(LF)(SN)  [TU2001_6D_180\2\H6.1]
R35  100k  [R0402\H0.4]
R36  100k  [R0402\H0.4]
R37  100k  [R0402\H0.4]
R51  30.1  [R0402\H0.4]
R52  30.1  [R0402\H0.4]
R72  30.1  [R0402\H0.4]
R73  30.1  [R0402\H0.4]
R74  30.1  [R0402\H0.4]
R75  30.1  [R0402\H0.4]
R76  30.1  [R0402\H0.4]
R117  100k  [R0402\H0.4]
R118  100k  [R0402\H0.4]
R119  100k  [R0402\H0.4]
R120  0  [R0402\H0.4]
R121  30.1  [R0402\H0.4]
R122  30.1  [R0402\H0.4]
R123  30.1  [R0402\H0.4]
R124  7.5k  [R0402\H0.4]
R125  0  [R0402\H0.4]
R126  7.5k  [R0402\H0.4]
R131  0  [R0402\H0.4]
R132  0  [R0402\H0.4]
R136  7.5k  [R0402\H0.4]
R139  10k  [R0402\H0.4]
R140  0  [R0402\H0.4]
R141  0  [R0402\H0.4]
R142  100k  [R0402\H0.4]
R143  100k  [R0402\H0.4]
R145  0  [R0402\H0.4]
R148  0  [R0402\H0.4]
R164  30.1  [R0402\H0.4]
R208  0  [R0402\H0.4]
R211  0  [R0402\H0.4]
R489  0  [R0402\H0.4]
R693  10k  [R0402\H0.4]
R694  10k  [R0402\H0.4]
R695  0  [R0402\H0.4]
R696  0  [R0402\H0.4]
R697  0  [R0402\H0.4]
R698  10k  [R0402\H0.4]
R699  10k  [R0402\H0.4]
R700  0  [R0402\H0.4]
R701  0  [R0402\H0.4]
R702  0  [R0402\H0.4]
R703  0  [R0402\H0.4]
R704  10k  [R0402\H0.4]
R705  0  [R0402\H0.4]
R706  10k  [R0402\H0.4]
R707  10k  [R0402\H0.4]
R708  10k  [R0402\H0.4]
R709  10k  [R0402\H0.4]
R771  0  [R0402\H0.4]
R772  0  [R0402\H0.4]
R788  100k  [R0402\H0.4]
R789  100k  [R0402\H0.4]
TP37  Testpoint  [ICT_50]
TP60  Testpoint  [ICT_50]
TP63  Testpoint  [ICT_50]
TP64  Testpoint  [ICT_50]
TP65  Testpoint  [ICT_50]
TP66  Testpoint  [ICT_50]
TP67  Testpoint  [ICT_50]
TP68  Testpoint  [ICT_50]
TP75  Testpoint  [ICT_50]
TP76  Testpoint  [ICT_50]
TP77  Testpoint  [ICT_50]
TP78  Testpoint  [ICT_50]
TP79  Testpoint  [ICT_50]
TP80  Testpoint  [ICT_50]
TP81  Testpoint  [ICT_50]
TP82  Testpoint  [ICT_50]
TP83  Testpoint  [ICT_50]
TP94  Testpoint  [ICT_50]
TP95  Testpoint  [ICT_50]
TP96  Testpoint  [ICT_50]
TP97  Testpoint  [ICT_50]
TP98  Testpoint  [ICT_50]
TP99  Testpoint  [ICT_50]
TP100  Testpoint  [ICT_50]
TP101  Testpoint  [ICT_50]
TP102  Testpoint  [ICT_50]
TP234  Testpoint  [ICT_50]
TP235  Testpoint  [ICT_50]
TP236  Testpoint  [ICT_50]
TP237  Testpoint  [ICT_50]
TP238  Testpoint  [ICT_50]
TP266  Testpoint  [ICT_50]
TP267  Testpoint  [ICT_50]
U39  DLPC3439  [VFBGA201\0.8\H1]  (sections A,B,C,D,E,F,G,H)
U40  DLPC3439  [VFBGA201\0.8\H1]  (sections A,B,C,D,E,F,G,H)
U52  SN74AUP1G07DCK  [MCP5\0.65\H1.1]
U53  SN74AUP1G07DCK  [MCP5\0.65\H1.1]
U54  SN74AUP1G07DCK  [MCP5\0.65\H1.1]
U55  SN74AUP1G07DCK  [MCP5\0.65\H1.1]
U56  SN74AUP1G07DCK  [MCP5\0.65\H1.1]
U63  SN74AUP1G07DCK  [MCP5\0.65\H1.1]
sheet P10: DLPA3005_PMIC & LED Driver
C300  10uF  [C0603\H0.9]
C301  22uF  [C1210\H2.8]
C302  22uF  [C1210\H2.8]
C303  22uF  [C1210\H2.8]
C304  22uF  [C1210\H2.8]
C305  10uF  [C1210\H2.8]
C306  1uF  [C0603\H0.9]
C307  22uF  [C1210\H2.8]
C308  0.1uF  [C0402\H0.55]
C309  1200pF  [C1206\H1.8]
C310  0.01uF  [C0402\H0.55]
C311  15pF  [C0402\H0.55]
C312  1uF  [C0603\H0.9]
C313  22uF  [C1210\H2.8]
C314  22uF  [C1210\H2.8]
C315  22uF  [C1210\H2.8]
C317  0.47uF  [C0603\H0.9]
C318  0.33uF  [C0402\H0.55]
C319  1uF  [C0603\H0.9]
C320  1uF  [C0402\H0.55]
C321  4300pF  [C0603\H0.9]
C322  0.1uF  [C0402\H0.55]
C323  10uF  [C0805\H1.35]
C324  10uF  [C1210\H2.8]
C325  0.33uF  [C0402\H0.55]
C326  0.1uF  [C0402\H0.55]
C327  1uF  [C0603\H0.9]
C328  1uF  [C0603\H0.9]
C329  10uF  [C0603\H0.9]
C330  2.2uF  [C0402\H0.55]
C331  4.7uF  [C0402\H0.55]
C332  1uF  [C0603\H0.9]
C333  10uF  [C0603\H0.9]
C334  0.1uF  [C0402\H0.55]
C336  22uF  [C1210\H2.8]
C337  22uF  [C1210\H2.8]
C340  22uF  [C0603\H0.9]
C341  22uF  [C0603\H0.9]
C342  470pF  [C0603\H0.9]
C346  0.1uF  [C0402\H0.55]
C348  22uF  [C1210\H2.8]
C349  22uF  [C1210\H2.8]
C352  470pF  [C0603\H0.9]
C353  22uF  [C0603\H0.9]
C354  22uF  [C0603\H0.9]
C358  1uF  [C0402\H0.55]
C360  1uF  [C0402\H0.55]
C363  1uF  [C0402\H0.55]
C367  1uF  [C0402\H0.55]
C370  1000pF  [C0603\H0.9]
D50  B240A-13-F  [DO214\SMA\H2.44]
D51  MBR0540  [SOD123\2A1C\3.75X1.6\H1.45]
D52  B240A-13-F  [DO214\SMA\H2.44]
D53  ESDA18-1K  [SOD523\2A1C\1.2X0.8\H0.7]
D54  ESDA18-1K  [SOD523\2A1C\1.2X0.8\H0.7]
D55  ESDA18-1K  [SOD523\2A1C\1.2X0.8\H0.7]
D58  B0530WS-7  [SOD323\2A1C\H1.1]
D59  B0530WS-7  [SOD323\2A1C\H1.1]
ED20  PESD5V0U1BL  [SOD882\2A1C\H0.5]
J40  78048-1043 Molex  [CON10_90\87438\1.5\H4.45]
J41  78048-1043 Molex  [CON10_90\87438\1.5\H4.45]
J42  78048-1043 Molex  [CON10_90\87438\1.5\H4.45]
J45  053261-0271 Molex  [TU1252_2S_90\1.25\H3.4]
L14  1.5uH  [IND\13.9X13.5\H5.2]
L15  10uH  [IND\MMD-04BZ\H2]
L16  3.3uH  [IND\MMD-06CZ\H3]
L18  3.3uH  [IND\MMD-06CZ\H3]
Q15  CSD17309Q3  [SON8\CSD16406Q3\0.65\H1.1]
Q16  CSD17501Q5A  [SON8\CSD17501Q5A\H1.1]
Q17  CSD17501Q5A  [SON8\CSD17501Q5A\H1.1]
Q18  CSD17501Q5A  [SON8\CSD17501Q5A\H1.1]
Q19  CSD17501Q5A  [SON8\CSD17501Q5A\H1.1]
R570  3.9  [R0603\H0.55]
R571  0  [R0402\H0.4]
R572  3.9  [R0603\H0.55]
R574  30k/1%  [R0402\H0.4]
R575  0  [R1206\H0.65]
R576  100k  [R0402\H0.4]
R578  3.9  [R1210\H0.65]
R579  0  [R0402\H0.4]
R580  10  [R0402\H0.4]
R581  0  [R0402\H0.4]
R582  10  [R0402\H0.4]
R583  0  [R0402\H0.4]
R584  30.1/1%  [R0402\H0.4]
R585  0  [R0603\H0.55]
R586  0  [R0603\H0.55]
R587  0  [R0603\H0.55]
R591  10k/1%  [R0402\H0.4]
R592  10k/1%  [R0402\H0.4]
R595  0.009  [R2512\H0.7]
R596  0  [R1206\H0.65]
R598  10  [R0603\H0.55]
R600  0  [R1206\H0.65]
R602  10  [R0603\H0.55]
R604  0  [R0402\H0.4]
R606  0  [R1206\H0.65]
R608  0  [R1206\H0.65]
R609  0  [R0402\H0.4]
R610  0  [R0402\H0.4]
R611  300  [R0402\H0.4]
R617  10k  [R0402\H0.4]
R650  0  [R0402\H0.4]
TP160  Testpoint  [ICT_50]
TP162  Testpoint  [ICT_50]
TP163  Testpoint  [ICT_50]
TP164  Testpoint  [ICT_50]
TP165  Testpoint  [ICT_50]
TP166  Testpoint  [ICT_50]
TP167  Testpoint  [ICT_50]
TP168  Testpoint  [ICT_50]
TP169  Testpoint  [ICT_50]
TP170  Testpoint  [ICT_50]
TP171  Testpoint  [ICT_50]
TP172  Testpoint  [ICT_50]
TP173  Testpoint  [ICT_50]
TP174  Testpoint  [ICT_50]
TP175  Testpoint  [ICT_50]
TP176  Testpoint  [ICT_50]
TP177  Testpoint  [ICT_50]
TP178  Testpoint  [ICT_50]
TP180  Testpoint  [ICT_50]
TP181  Testpoint  [ICT_50]
TP182  Testpoint  [ICT_50]
TP183  Testpoint  [ICT_50]
TP184  Testpoint  [ICT_50]
TP185  Testpoint  [ICT_50]
TP187  Testpoint  [ICT_50]
TP189  Testpoint  [ICT_50]
TP191  Testpoint  [ICT_50]
TP209  Testpoint  [ICT_50]
TP210  Testpoint  [ICT_50]
TP211  Testpoint  [ICT_50]
U35  DLPA3005  [PQFP100\0.5\H1.2]  (sections -1,-2)

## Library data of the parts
C394 = CAP_0.1uF_0603_1: Ceramic CAP X7R 6.3V 0.1uF
C395 = CAP_0.1uF_0603_3: Ceramic CAP X7R 6.3V 0.1uF
C396 = CAP_0.1uF_0603_4: Ceramic CAP X7R 6.3V 0.1uF
C397 = CAP_0.1uF_0603_2: Ceramic CAP X7R 6.3V 0.1uF
C398 = CAP_0.1uF_0603: Ceramic CAP X7R 6.3V 0.1uF
ED20 ED23-ED27 = DIODE_SCHOTTKY31_4
FB22 = FB_4: ID: 159352; device: R0603
FB23 = FB_3: ID: 159352; device: R0603
FB24 = FB_2: ID: 159352; device: R0603
FB25 = FB_1: ID: 159352; device: R0603
FB26 = FB: ID: 159352; device: R0603
J48 = EM,HDR,6P,1R,2X: DigiKey: SAM1029-06-ND; DigiReel: ---; Family: electro/mechanical; Index PN: 678; Install: Y; Lead Style: TH; MFG: Samtec; P/D_NUM: TSW-106-07-G-S; Part Number: TSW-106-07-G-S; Part Specific: CONN HEADER 6POS .100in SGL GOLD; Pin Cnt: 6; Pin Spacing: 100mil; Row Cnt: 1; Type: header; VENDOR: Samtec
R35-R37 R51 R52 R72-R76 R117-R126 R136 R139-R143 R164 R208 R211 = RESISTOR_SM
R131 R132 R145 R148 R489 R617 R695 R700 R701 R705 R788 R789 = RESISTOR_SM: DNI: DNI
R693 = R_v4_1
R694 = R_v4_10: DNI: DNI
R696 = R_v4_12
R697 = R_v4_5: DNI: DNI
R698 = R_v4_6: DNI: DNI
R699 = R_v4_9
R702 = R_v4_4
R703 = R_v4: DNI: DNI
R704 = R_v4_11
R706 = R_v4_7
R707 = R_v4_8: DNI: DNI
R708 = R_v4_2
R709 = R_v4_3: DNI: DNI
R771 = R: ROHS CHIP RES  1/16W 150K 5% SMT 0402; DNI: DNI; P/N: 01.00036G503
R772 = R_1: ROHS CHIP RES  1/16W 150K 5% SMT 0402; DNI: DNI; P/N: 01.00036G503
TP37 TP60 TP63-TP68 TP75-TP83 TP94-TP102 = T_POINT_R: Desc: TEST POINT, T/H, BLACK; Dist: Digi-Key; Dist p/n: 5001K-ND; Mfr: Keystone Electronics; Mfr p/n: 5001
TP160 TP162-TP168 TP171 TP173 TP175-TP178 TP180-TP185 TP187 TP189 TP191 TP211 TP234-TP238 TP266 TP267 = EM,TESTPOINT: Install: DNI; MFG: -- NOT A PART --; Part Specific: TP_20RD10; Type: testpoint via; Vendor: -- NOT A PART --
U39 = TIDLP,DPP3438_6: DigiKey: ---; DigiReel: ---; Family: processor; Index PN: 1176; Lead Style: SMT; MFG: Texas Instruments; P/D_NUM: 2512737-0092; Package: Master; Part Number: 2512737-0092; Part Specific: IC, DPP3439 ASIC, DLP-PICO PROCESSOR; Type: dlp; Vendor: Texas Instruments; Install: Y
U40 = TIDLP,DPP3438_6: DigiKey: ---; DigiReel: ---; Family: processor; Index PN: 1176; Lead Style: SMT; MFG: Texas Instruments; P/D_NUM: 2512737-0092; Package: Slave; Part Number: 2512737-0092; Part Specific: IC, DPP3439 ASIC, DLP-PICO PROCESSOR; Type: dlp; Vendor: Texas Instruments; Install: Y
U52-U56 = TMP_0: DigiKey: 296-18256-1-ND; DigiReel: 296-18256-6-ND; Family: logic; Index PN: 1027; Install: Y; Lead Style: SMT; MFG: Texas Instruments; P/D_NUM: SN74AUP1G07DCKR; Part Number: SN74AUP1G07DCKR; Part Specific: IC BUFF/DVR LOW PWR N-INV SC705, open drain; Type: buffer
U63 = TMP_1_v2: DNI: DNI; DigiKey: 296-18256-1-ND; DigiReel: 296-18256-6-ND; Family: logic; Index PN: 1027; Install: Y; Lead Style: SMT; MFG: Texas Instruments; P/D_NUM: SN74AUP1G07DCKR; Part Number: SN74AUP1G07DCKR; Part Specific: IC BUFF/DVR LOW PWR N-INV SC705, open drain; Type: buffer
C300 = PAS,CAP,NP,large: DigiKey: 445-8920-1-ND; DigiReel: 445-8920-6-ND; Family: passive; Lead Style: SMT; MFG: TDK; Material: x5r; P/D_NUM: C1005X5R0J106M050BC; Part Number: C1005X5R0J106M050BC; Part Specific: CAP CER 10UF 6.3V 20% X5R 0402; TOLERANCE: 20%; Type: capacitor; VENDOR: TDK; VPC: 10V; Voltage: 6.3V
C301-C305 C324 C336 C337 C348 C349 = PAS,CAP,NP,large: DigiKey: 490-7207-1-ND; DigiReel: 490-7207-6-ND; Family: passive; Lead Style: SMT; MFG: Murata; Material: X5R; P/D_NUM: GRM219R61E106KA12D; Part Number: GRM219R61E106KA12D; Part Specific: CAP CER 10UF 25V 10% X5R 0805; TOLERANCE: 10%; Type: capacitor; VENDOR: Murata; VPC: 25V; Voltage: 25V
C306 C312 C327 C328 C332 C358 C363 = PAS,CAP,NP,large: DigiKey: 445-9081-1-ND; DigiReel: 445-9081-6-ND; Family: passive; Lead Style: SMT; MFG: TDK; Material: X5R; P/D_NUM: C1005X5R1E105M050BC; Part Number: C1005X5R1E105M050BC; Part Specific: CAP CER 1UF 25V 20% X5R 0402; TOLERANCE: 20%; Type: capacitor; VENDOR: TDK; VPC: 25V; Voltage: 25V
C307 C313 = PAS,CAP,NP,large: DigiKey: 445-8028-1-ND; DigiReel: 445-8028-6-ND; Family: passive; Lead Style: SMT; MFG: TDK; Material: X5R; P/D_NUM: C1608X5R0J226M080AC; Part Number: C1608X5R0J226M080AC; Part Specific: CAP CER 22UF 6.3V 20% X5R 0603; TOLERANCE: 20%; Type: capacitor; VENDOR: TDK; VPC: 16V; Voltage: 6.3V
C308 C311 C322 C334 C346 = PAS,CAP,NP,large: DigiKey: 445-4952-1-ND; DigiReel: 445-4952-6-ND; Family: passive; Index PN: 681; Lead Style: SMT; MFG: TDK; Material: x7r; P/D_NUM: C1005X7R1C104K050BC; Part Number: C1005X7R1C104K050BC; Part Specific: CAP CER .1UF 16V X7R 0402; TOLERANCE: 10%; Type: capacitor; VENDOR: TDK; VPC: 16V; Voltage: 16V
C309 = PAS,CAP,NP,large: DigiKey: 478-1493-1-ND; DigiReel: 478-1493-6-ND; Family: passive; Install: Y; Lead Style: SMT; MFG: AVX; Material: npo; P/D_NUM: 12065A122JAT2A; Part Number: 12065A122JAT2A; Part Specific: CAP CER 1200PF 50V 5% NP0 1206; TOLERANCE: 5%; Type: capacitor; VENDOR: AVX; VPC: 50V; Voltage: 50V
C310 = PAS,CAP,NP,large: DigiKey: 445-1262-1-ND; DigiReel: 445-1262-6-ND; Family: passive; Index PN: 908; Lead Style: SMT; MFG: TDK; Material: x7r; P/D_NUM: C1005X7R1C103K; Part Number: C1005X7R1C103K; Part Specific: CAP CER 10000PF 16V X7R 10% 0402; TOLERANCE: 10%; Type: capacitor; VENDOR: TDK; VPC: 16V; Voltage: 16V
C314 C315 = PAS,CAP,NP,large: DNI: DNI; DigiKey: 445-8028-1-ND; DigiReel: 445-8028-6-ND; Family: passive; Lead Style: SMT; MFG: TDK; Material: X5R; P/D_NUM: C1608X5R0J226M080AC; Part Number: C1608X5R0J226M080AC; Part Specific: CAP CER 22UF 6.3V 20% X5R 0603; TOLERANCE: 20%; Type: capacitor; VENDOR: TDK; VPC: 16V; Voltage: 6.3V
C317 C319 = PAS,CAP,NP,large: DigiKey: 445-8020-1-ND; DigiReel: 445-8020-6-ND; Family: passive; Lead Style: SMT; MFG: TDK; Material: X5R; P/D_NUM: C1005X5R1E474K050BB; Part Number: C1005X5R1E474K050BB; Part Specific: CAP CER 0.47UF 25V 10% X5R 0402; Type: capacitor; VENDOR: TDK; VPC: 25V; Voltage: 25V
C318 = CAP_0.1uF_0603_1: Ceramic CAP X7R 6.3V 0.1uF; DNI: DNI
C320 C329 C333 C360 C367 = PAS,CAP,NP,large: DigiKey: 445-4991-1-ND; DigiReel: 445-4991-6-ND; Family: passive; Index PN: 916; Lead Style: SMT; MFG: TDK; Material: x5r; P/D_NUM: C1005X5R1A105M; Part Number: C1005X5R1A105M; Part Specific: CAP CER 1.0UF 10V X5R 0402; TOLERANCE: 20%; Type: capacitor; VENDOR: TDK; VPC: 10V
C321 C370 = PAS,CAP,NP,large: DigiKey: 445-1291-1-ND; DigiReel: 445-1291-6-ND; Family: passive; Install: Y; Lead Style: SMT; MFG: TDK; Material: npo; P/D_NUM: C1608C0G1H681J080AA; Part Number: C1608C0G1H681J080AA; Part Specific: CAP CER 680PF 50V 5% NP0 0603; TOLERANCE: 5%; Type: capacitor; VENDOR: TDK; VPC: 50V; Voltage: 50V
C323 = PAS,CAP,NP,large_0: DigiKey: 490-7207-1-ND; DigiReel: 490-7207-6-ND; Family: passive; Lead Style: SMT; MFG: Murata; Material: X5R; P/D_NUM: GRM219R61E106KA12D; Part Number: GRM219R61E106KA12D; Part Specific: CAP CER 10UF 25V 10% X5R 0805; TOLERANCE: 10%; Type: capacitor; VENDOR: Murata; VPC: 25V; Voltage: 25V
C325 = CAP_0.1uF_0603: Ceramic CAP X7R 6.3V 0.1uF; DNI: DNI
C326 = PAS,CAP,NP,large: DigiKey: 445-4952-1-ND; DigiReel: 445-4952-6-ND; Family: passive; Index PN: 681; Lead Style: SMT; MFG: TDK; Material: x7r; P/D_NUM: C1005X7R1C104K050BC; Part Number: C1005X7R1C104K050BC; Part Specific: CAP CER .1UF 16V X7R 0402; TOLERANCE: 10%; Type: capacitor; VENDOR: TDK; VPC: 16V; Voltage: 25V
C330 = PAS,CAP,NP,large: DigiKey: 445-4999-1-ND; DigiReel: 445-4999-6-ND; Family: passive; Index PN: 915; Lead Style: SMT; MFG: TDK; Material: X5R; P/D_NUM: C1005X5R0J225M; Part Number: C1005X5R0J225M; Part Specific: CAP CER 2.2UF 6.3V 20% X5R 0402; TOLERANCE: 20%; Type: capacitor; VENDOR: TDK; VPC: 6.3V; Voltage: 6.3V
C331 = PAS,CAP,NP,large: DigiKey: 445-7395-1-ND; DigiReel: 445-7395-6-ND; Family: passive; Lead Style: SMT; MFG: TDK; Material: X5R; P/D_NUM: C1005X5R0J475M050BC; Part Number: C1005X5R0J475M050BC; Part Specific: CAP CER 4.7UF 6.3V 20% X5R 0402; TOLERANCE: 20%; Type: capacitor; VENDOR: TDK; VPC: 6.3V; Voltage: 6.3V
C340 C341 C353 C354 = PAS,CAP,NP,large: DigiKey: 445-8028-1-ND; DigiReel: 445-8028-6-ND; Family: passive; Lead Style: SMT; MFG: TDK; Material: X5R; P/D_NUM: C1608X5R0J226M080AC; Part Number: C1608X5R0J226M080AC; Part Specific: CAP CER 22UF 6.3V 20% X5R 0603; TOLERANCE: 20%; Type: capacitor; VENDOR: TDK; VPC: 6.3V; Voltage: 6.3V
C342 C352 = PAS,CAP,NP,large: DigiKey: 445-1289-1-ND; DigiReel: 445-1289-6-ND; Family: passive; Install: Y; Lead Style: SMT; MFG: TDK; Material: npo; P/D_NUM: C1608C0G1H471J080AA; Part Number: C1608C0G1H471J080AA; Part Specific: CAP CER 470PF 50V 5% NP0 0603; TOLERANCE: 5%; Type: capacitor; VENDOR: TDK; VPC: 50V; Voltage: 50V
D50 D52 = DIODE_SCHOTTKY31_3: DNI: DNI
D51 = PAS,DIODE,SCHOTTKY,large: DigiKey: MBR0540CT-ND; DigiReel: MBR0540DKR-ND; Family: passive; Lead Style: SMT; MFG: Fairchild Semiconductor; Part Specific: SCHOTTKY RECT 40V 0.5A SOD123; Type: diode,schottky; VENDOR: Fairchild Semiconductor; VPC: 0.5A; Voltage: 40V
D53-D55 = PAS,DIODE,TVS,large: DigiKey: 497-10767-1-ND; DigiReel: 497-10767-6-ND; Lead Style: SMT; MFG: STMicroelectronics; Part Specific: DIODE TVS 18V 450W SOD523; Type: Diode,TVS; VENDOR: STMicroelectronics; VPC: 18V; Voltage: 18V
D58 D59 = DIODE_SCHOTTKY31_1
J40-J42 = CONN_SOCKET_10
J45 = CONN_SOCKET_2_1
L14 = PAS,INDUCTOR,_large: DigiKey: ---; DigiReel: ---; Family: passive; Lead Style: SMT; MFG: Coilcraft; P/D_NUM: XAL7030-272MEB; Part Number: MMD-12EZ-1R5M-V1; Part Specific: Inductor 2.7uH 9.2A 20% SMD; Type: inductor; VENDOR: Coilcraft; VPC: 9.2A
L15 = PAS,INDUCTOR,_large: Family: passive; Lead Style: SMT; MFG: Coilcraft; P/D_NUM: LPS4018-103MLB; Part Number: 03.10003G352--10uH 1.6A-MMD-04BZ-100M-S1; Part Specific: INDUCTOR 10UH 20% 0.9A SMD; Type: inductor; VENDOR: Coilcraft; VPC: 0.9A
L16 L18 = PAS,INDUCTOR,_large: DigiKey: 541-1221-1-ND; DigiReel: 541-1221-6-ND; Family: passive; Lead Style: SMT; MFG: Vishay Dale; P/D_NUM: IHLP2020BZER3R3M11; Part Number: MMD-06CZ-3R3M-V1; Part Specific: INDUCTOR POWER 3.3UH 4.1A SMD; Type: inductor; VENDOR: Vishay Dale; VPC: 4.1A
Q15-Q19 = ANA,FET,CSD16342Q5A: DigiKey: 296-30314-1-ND; DigiReel: 296-30314-6-ND; Family: analog; Install: Y; Lead Style: SMT; MFG: Texas Instruments; P/D_NUM: CSD16342Q5A; Part Number: CSD16342Q5A; Part Specific: MOSFET N-CH 25V 100A 8SON; Pin Cnt: 8; Type: MOSFET; VENDOR: Texas Instruments; VPC: 100A; Voltage: 25V
R570 R572 R580 R582 R585-R587 R604 R611 R650 = PAS,R,large: DigiKey: P0.0JCT-ND; DigiReel: P0.0JDKR-ND; Family: passive; Index PN: 687; Install: DNI; Lead Style: SMT; MFG: Panasonic; Material: chip; P/D_NUM: ERJ-2GE0R00X; Part Number: ERJ-2GE0R00X; Part Specific: RES 0.0 OHM 1/16W 0402 SMD; Power: 1/16W; Type: resistor; VPC: 1/16W; Vendor: Panasonic
R571 = PAS,R,large: DigiKey: P0.0JCT-ND; DigiReel: P0.0JDKR-ND; Family: passive; Index PN: 687; Lead Style: SMT; MFG: Panasonic; Material: chip; P/D_NUM: ERJ-2GE0R00X; Part Number: ERJ-2GE0R00X; Part Specific: RES 0.0 OHM 1/16W 0402 SMD; Power: 1/16W; Type: resistor; VPC: 1/16W; Vendor: Panasonic
R574 = PAS,R,large: DigiKey: P30.0KLCT-ND; DigiReel: P30.0KLDKR-ND; Family: passive; Index PN: 909; Lead Style: SMT; MFG: Panasonic; Material: chip; P/D_NUM: ERJ-2RKF3002X; Part Number: ERJ-2RKF3002X; Part Specific: RES 30.0K OHM 1/10W 1% 0402 SMD; Power: 1/16W; Tolerance: 1%; Type: resistor; VPC: 1/16W; Vendor: Panasonic
R575 R596 R600 R606 = PAS,R,large: DigiKey: 541-1890-1-ND; DigiReel: 541-1890-6-ND; Family: passive; Install: DNI; Lead Style: SMT; MFG: Vishay; Material: chip; P/D_NUM: RCG12060000Z0EA; Part Number: RCG12060000Z0EA; Part Specific: RES 0.0 OHM 3.5A JUMP 1206 SMD; Power: 1/4W; Type: resistor; VENDOR: Panasonic; VPC: 1/16W
R576 = PAS,THERMISTOR,large: DigiKey: 490-4803-1-ND; DigiReel: 490-4803-6-ND; Family: passive; Index PN: 910; Lead Style: SMT; MFG: Murata; P/D_NUM: NCP15WF104F03RC; Part Number: NCP15WF104F03RC; Part Specific: THERMISTOR 100K OHM NTC 0402 SMD; TOLERANCE: 1%; Type: thermistor; VENDOR: Murata
R578 = PAS,R,large: DigiKey: RHM3.9AXCT-ND; DigiReel: RHM3.9AXDKR-ND; Family: passive; Install: Y; Lead Style: SMT; MFG: Rohm; Material: chip; P/D_NUM: ESR25JZPJ3R9; Part Number: ESR25JZPJ3R9; Part Specific: RES 3.9 OHM 1/2W 5% 1210 SMD; Power: 1/2W; TOLERANCE: 5%; Type: resistor; VPC: 1/2W; Vendor: Rohm
R579 = R_1: Part Description: RESISTOR 10K OHMS 1/10W 5% 0603; Part Type: 5%\0603; Sierra Part#: 1200100-103; Tolerance: 5%
R581 = R: DNI: DNI
R583 = R_2: Part Description: RESISTOR 10K OHMS 1/10W 5% 0603; Part Type: 5%\0603; Sierra Part#: 1200100-103; Tolerance: 5%
R584 R591 R592 = PAS,R,large: DigiKey: P10.0KLCT-ND; DigiReel: P10.0KLDKR-ND; Family: passive; Index PN: 680; Lead Style: SMT; MFG: Panasonic; Material: chip; P/D_NUM: ERJ-2RKF1002X; Part Number: ERJ-2RKF1002X; Part Specific: RES 10K OHM 1/10W 1% 0402 SMD; Power: 1/16W; Tolerance: 1%; Type: resistor; VPC: 1/16W; Vendor: Panasonic
R595 = PAS,R,large: DigiKey: 989-1041-1-ND; DigiReel: 989-1041-6-ND; Family: passive; Lead Style: SMT; MFG: TT Electronics; Material: chip; P/D_NUM: LRC-LRF2010LF-01-R025F; Part Number: LRC-LRF2010LF-01-R025F; Part Specific: RES .025 OHM 1W 1% 2010 SMD; Tolerance: 1%; Type: resistor; VPC: 3W; Vendor: TT Electronics
R598 R602 = PAS,R,large: DigiKey: RHM10.0ADCT-ND; DigiReel: RHM10.0ADDKR-ND; Family: passive; Install: Y; Lead Style: SMT; MFG: Rohm; Material: chip; P/D_NUM: ESR03EZPF10R0; Part Number: ESR03EZPF10R0; Part Specific: RES 10 OHM 1/4W 1% 0603 SMD; Power: 1/4W; TOLERANCE: 1%; Type: resistor; VPC: 1/4W; Vendor: Panasonic
R608 = PAS,R,large: DNI: DNI; Family: passive; Install: DNI; Lead Style: SMT; MFG: Vishay; Material: chip; P/D_NUM: RCG12060000Z0EA; Part Number: RCG12060000Z0EA; Part Specific: RES 0.0 OHM 3.5A JUMP 1206 SMD; Power: 1/4W; Type: resistor; VENDOR: Panasonic; VPC: 1/16W
R609 R610 = PAS,R,large: DNI: DNI; DigiKey: P0.0JCT-ND; DigiReel: P0.0JDKR-ND; Family: passive; Index PN: 687; Install: DNI; Lead Style: SMT; MFG: Panasonic; Material: chip; P/D_NUM: ERJ-2GE0R00X; Part Number: ERJ-2GE0R00X; Part Specific: RES 0.0 OHM 1/16W 0402 SMD; Power: 1/16W; Type: resistor; VPC: 1/16W; Vendor: Panasonic
TP169 TP170 TP172 TP174 TP209 TP210 = BF,HOLE,PLATED,TESTPIN: DigiKey: ---; DigiReel: ---; Family: board feature; Index PN: 377; Install: DNI; Lead Style: TH; MFG: -- NOT A PART --; Part Specific: TP; Type: hole,plated; Vendor: -- NOT A PART --
U35 = TIDLP,PAD3000_V2_2: Color: Default; Install: Y; Location X-Coordinate: 0; Location Y-Coordinate: 0; MFG: Texas Instruments; Part Number: PAD3005; Part Specific: IC PMIC LED DRIVER; Pin Cnt: 100; Power Pins Visible: False; Primitive: DEFAULT; SPLIT_INST: TRUE; SWAP_INFO: (S1+S2); Vendor: Texas Instruments

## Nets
DGND: C300.1(P) C301.2(N) C302.2(N) C303.2(N) C304.2(N) C305.2(N) C306.2(N) C307.2(N) C310.2(N) C312.2(N) C313.2(N) C314.2(N) C315.2(N) C317.2(N) C318.1 C319.2(N) C320.2(N) C321.2(N) C322.2(N) C323.2(N) C324.2(N) C325.1 C326.2(N) C327.2(N) C328.2(N) C329.2(N) C330.1(P) C331.1(P) C332.2(N) C333.2(N) C336.2(N) C337.2(N) C340.2(N) C341.2(N) C348.2(N) C349.2(N) C353.2(N) C354.2(N) C358.2(N) C360.2(N) C363.2(N) C367.2(N) C394.2 C395.2 C396.2 C397.2 C398.2 D52.1(ANODE) D53.2(P2) D54.2(P2) D55.2(P2) ED20.2(ANODE) ED23.2(ANODE) ED24.2(ANODE) ED25.2(ANODE) ED26.2(ANODE) ED27.2(ANODE) J45.2 J45.3 J45.4 J48.6 Q16.1(S1) Q16.2(S2) Q16.3(S3) R136.2 R139.2 R142.1 R143.1 R576.2 R578.1(N1) R582.2(N2) R595.1(N1) R598.2(N2) R602.2(N2) U35.4(DRST_PGND) U35.12(RLIM_BOT_K_2) U35.14(RLIM_BOT_K_1) U35.32(ILLUM_A_PGND) U35.37(ILLUM_B_PGND) U35.42(THERMAL_PAD) U35.54(PWR7_PGND) U35.59(DGND) U35.62(PWR6_PGND) U35.70(PWR5_PGND) U35.73(PWR2_PGND) U35.86(AGND) U35.93(PWR1_PGND) U52.3(GND) U53.3(GND) U54.3(GND) U55.3(GND) U56.3(GND) U63.3(GND) ; also on sheet 1 2 5 6 7 8 9 10
P5V: R606.2(N2) R694.2 R697.2 R703.2 R707.2 R709.2 ; also on sheet 2 6 8 10
V2P5: C330.2(N) TP183.1(P1) U35.91(SUP_2P5V)
V5P0: C331.2(N) TP182.1(P1) U35.92(SUP_5P0V)
VIN: C301.1(P) C302.1(P) C303.1(P) C304.1(P) C305.1(P) C306.1(P) C323.1(P) C324.1(P) C327.1(P) C328.1(P) C332.1(P) C336.1(P) C337.1(P) C348.1(P) C349.1(P) D50.2(CATHODE) Q15.5(D4) Q15.6(D3) Q15.7(D2) Q15.8(D1) R608.2(N2) U35.5(DRST_VIN) U35.8(ILLUM_VIN) U35.30(ILLUM_A_VIN) U35.34(ILLUM_B_VIN) U35.75(PWR2_VIN) U35.83(PWR_VIN) U35.85(VIN_SYSPWR) U35.96(PWR1_VIN) ; also on sheet 8
VIN_LDO: C358.1(P) C363.1(P) R606.1(N1) R608.1(N1) U35.88(PWR3_VIN) U35.90(PWR4_VIN)
3D_GLASS_SYNC: R772.1 TP79.1(TP) U40.G15(GPIO_9)
CH1_GATE_CTRL: R585.2(N2) U35.19(CH1_GATE_CTRL)
CH1_GATE_RED: Q17.4(G) R585.1(N1) TP177.1(P1)
CH2_GATE_CTRL: R586.2(N2) U35.20(CH2_GATE_CTRL)
CH2_GATE_GRN: Q18.4(G) R586.1(N1) TP178.1(P1)
CH3_GATE_BLU: Q19.4(G) R587.1(N1) TP181.1(P1)
CH3_GATE_CTRL: R587.2(N2) U35.21(CH3_GATE_CTRL)
CMP_OUT: TP99.1(TP) U35.81(ACMPR_OUT) U39.A12(CMP_OUT)
CMP_PWM: R591.1(N1) TP100.1(TP) U39.A15(CMP_PWM)
CMPR_REF: R592.2(N2) U35.82(ACMPR_REF)
CW_CLK: R581.1 U35.43(CLK_OUT)
CW_PWM: R581.2 U35.44(CW_PWM_OUT)
DA_SYNC_FSD12: TP267.1(P1) U39.K15(GPIO_15) U40.K15(GPIO_15)
DPP_P1P1V: R596.2(N2) TP187.1(P1) ; also on sheet 1
DPP_P1P8V: C320.1(P) C322.1(P) C397.1 C398.1 R124.2 R126.2 R208.2 R211.2 R600.2(N2) R617.1 R698.2 R788.1 TP189.1(P1) U35.45(SPI_VIN) U55.5(PWR) U56.5(PWR) ; also on sheet 1 5 6 9 10
DPP_P2P5V: R604.2(N2) TP191.1(P1)
DPP_VSYNC_OUT: FB26.2 R708.1 R709.1 TP238.1(P1) U56.4(Y) ; also on sheet 2
DRST_5P5V: C300.2(N) TP160.1(P1) U35.3(DRST_5P5V)
DRST_HS: D51.1(P1) L15.1 U35.6(DRST_HS_IND)
DRST_LS: L15.2 U35.2(DRST_LS_IND)
EXT_RLIM: Q17.1(S1) Q17.2(S2) Q17.3(S3) Q18.1(S1) Q18.2(S2) Q18.3(S3) Q19.1(S1) Q19.2(S2) Q19.3(S3) R595.2(N2) U35.13(RLIM_K_2) U35.15(RLIM_K_1)
GPIO10: R611.2(N2) TP64.1(TP) U39.H14(GPIO_10)
GPIO_0: R120.1 U39.C14(GPIO_0)
GPIO_1: R117.1 R121.1 U39.C15(GPIO_1)
GPIO_2: R118.1 R122.1 U39.D14(GPIO_2)
GPIO_3: R119.1 R123.1 U39.D15(GPIO_3)
GPIO_4: R124.1 U39.E14(GPIO_4)
GPIO_5: R701.1 TP60.1(TP) U39.E15(GPIO_5)
GPIO_7: R148.1 R610.2(N2)
GPIO_9: R489.2 U39.G15(GPIO_9)
GPIO_13: TP63.1(TP) U39.J15(GPIO_13)
HBT_ICLK: R72.2 U39.L14(GPIO_16)
HBT_IDAT: R164.2 U39.L15(GPIO_17)
HBT_OCLK: R51.1 U39.M14(GPIO_18)
HBT_ODAT: R52.1 U39.M15(GPIO_19)
ILLUM_5P5V: C329.1(P) R580.1(N1) TP184.1(P1) U35.7(ILLUM_5P5V)
ILLUM_A_COMP1: C311.2(N) U35.38(ILLUM_A_COMP1)
ILLUM_A_COMP2: C311.1(P) U35.39(ILLUM_A_COMP2)
ILLUM_A_SW_L: C308.2(N) C309.1(P) C370.2(N) D50.1(ANODE) D52.2(CATHODE) L14.2 Q15.1(S1) Q15.2(S2) Q15.3(S3) Q16.5(D4) Q16.6(D3) Q16.7(D2) Q16.8(D1) R575.2(N2) TP163.1(P1)
ILLUM_B_BOOST: R580.2(N2) U35.33(ILLUM_B_BOOST)
ILLUM_B_COMP1: TP175.1(P1) U35.40(ILLUM_B_COMP1)
ILLUM_B_COMP2: TP176.1(P1) U35.41(ILLUM_B_COMP2)
ILLUM_B_SW: R582.1(N1) U35.36(ILLUM_B_SW)
ILLUM_BOOST: C308.1(P) U35.28(ILLUM_A_BOOST)
ILLUM_HS_DRV: D58.1(CATHODE) R570.2(N2) TP162.1(P1) U35.26(ILLUM_HSIDE_DRIVE)
ILLUM_HS_DRV_Q: C370.1(P) D58.2(ANODE) Q15.4(G) R570.1(N1)
ILLUM_LS_DRV: D59.1(CATHODE) R572.2(N2) TP164.1(P1) U35.27(ILLUM_LSIDE_DRIVE)
ILLUM_SW: R575.1(N1) U35.31(ILLUM_A_SW)
IT6801_VSYNC: R695.1 U52.2(A) ; also on sheet 6
ITE6801_VSYNC_OUT: FB22.2 R693.1 R694.1 R695.2 TP234.1(P1) U52.4(Y)
LABB_SAMPLE: R610.1(N1) U35.55(ACMPR_LABB_SAMPLE)
LED_ANODE: C307.1(P) C313.1(P) C314.1(P) C315.1(P) J40.6 J40.7 J40.8 J40.9 J40.10 J41.1 J41.2 J41.3 J41.4 J41.5 J42.1 J42.2 J42.3 J42.4 J42.5 L14.1 TP168.1(P1) U35.29(ILLUM_A_FB)
LED_ANODE_B: TP171.1(P1) U35.35(ILLUM_B_FB)
LED_BLU_CATHODE: D55.1(P1) J42.6 J42.7 J42.8 J42.9 J42.10 Q19.5(D4) Q19.6(D3) Q19.7(D2) Q19.8(D1)
LED_GRN_CATHODE: D54.1(P1) J41.6 J41.7 J41.8 J41.9 J41.10 Q18.5(D4) Q18.6(D3) Q18.7(D2) Q18.8(D1)
LED_RED_CATHODE: D53.1(P1) J40.1 J40.2 J40.3 J40.4 J40.5 Q17.5(D4) Q17.6(D3) Q17.7(D2) Q17.8(D1)
LED_SEL0: R140.2 U39.B15(LED_SEL_0)
LED_SEL1: R141.2 U39.B14(LED_SEL_1)
LED_SEL_0: R140.1 R143.2 TP101.1(TP) U35.60(CH_SEL_0)
LED_SEL_1: R141.1 R142.2 TP102.1(TP) U35.61(CH_SEL_1)
LLUM_LS_DRV_Q: C321.1(P) D59.2(ANODE) Q16.4(G) R572.1(N1)
LS2_PWR: R145.1 R583.1 TP210.1(P1)
LS_PWR: R489.1 R579.1 TP209.1(P1)
NORM_PARK_GPIO8: R125.2 R788.2 U39.G14(GPIO_8) U63.4(Y)
P3P3V: C394.1 R131.1 R132.1 R609.2(N2) R693.2 R696.2 R699.2 R702.2 R704.2 R706.2 R708.2 R771.1 R789.2 U52.5(PWR) U63.5(PWR) ; also on sheet 1 2 6 7 8 9 10
P3P3V_INTF: R650.2(N2) TP211.1(P1) ; also on sheet 1
PAD_RESETZ: U35.57(RESET_Z) ; also on sheet 10
PARKZ: R617.2 U35.58(INTZ) ; also on sheet 10
PROJ_ON: R125.1 R789.1 U35.56(PROJ_ON) U63.2(A) ; also on sheet 8
PWM_IN_CAP: C326.1(P) R591.2(N2) R592.1(N1) R611.1(N1)
PWR1_B: C334.1(P) U35.97(PWR1_BOOST)
PWR1_OUT: C340.1(P) C341.1(P) L16.2 R596.1(N1) U35.94(PWR1_FB)
PWR1_SW: C334.2(N) C342.2(N) L16.1 U35.95(PWR1_SWITCH)
PWR2_B: C346.1(P) U35.76(PWR2_BOOST)
PWR2_OUT: C353.1(P) C354.1(P) L18.2 R600.1(N1) U35.72(PWR2_FB)
PWR2_SW: C346.2(N) C352.2(N) L18.1 U35.74(PWR2_SWITCH)
PWR3_OUT: C360.1(P) R604.1(N1) U35.87(PWR3_OUT)
PWR4_OUT: C367.1(P) R609.1(N1) R650.1(N1) U35.89(PWR4_OUT)
PWR_5P5V: C333.1(P) TP185.1(P1) U35.84(PWR_5P5V)
S_CMP_OUT: R139.1 U40.A12(CMP_OUT)
S_GPIO_0: R73.1 U40.C14(GPIO_0)
S_GPIO_1: R35.1 R74.1 U40.C15(GPIO_1)
S_GPIO_2: R36.1 R75.1 U40.D14(GPIO_2)
S_GPIO_3: R37.1 R76.1 U40.D15(GPIO_3)
S_GPIO_4: R136.1 U40.E14(GPIO_4)
S_HBT_ICLK: R51.2 U40.L14(GPIO_16)
S_HBT_IDAT: R52.2 U40.L15(GPIO_17)
S_HBT_OCLK: R72.1 U40.M14(GPIO_18)
S_HBT_ODAT: R164.1 U40.M15(GPIO_19)
S_SPI1_CLK: R74.2 TP66.1(TP)
S_SPI1_CSZ0: R76.2 TP68.1(TP)
S_SPI1_DIN: R73.2 TP65.1(TP)
S_SPI1_DOUT: R75.2 TP67.1(TP)
SENS2: C310.1(P) R571.2(N2) TP170.1(P1) U35.78(ACMPR_IN_2)
SENS3: C318.2 R579.2 TP172.1(P1) U35.79(ACMPR_IN_3)
SENS_FOCUS: TP180.1(P1) U35.77(ACMPR_IN_1)
SENS_LABB: C325.2 R583.2 TP174.1(P1) U35.80(ACMPR_IN_LABB)
SEQ_SYNC: R126.1 TP266.1(P1) U39.K14(GPIO_14) U40.K14(GPIO_14)
SPI1_CLK: R121.2 TP95.1(TP) U35.46(SPI_CLK)
SPI1_CSZ0: R123.2 TP97.1(TP) U35.48(SPI_CS_Z)
SPI1_DIN: R120.2 R584.1(N1) TP94.1(TP)
SPI1_DOUT: R122.2 TP96.1(TP) U35.49(SPI_MOSI)
SPI_MISO: R584.2(N2) U35.47(SPI_MISO)
THERM_PWR: R574.2(N2) TP98.1(TP) U39.H15(GPIO_11)
THERMISTOR_P: ED20.1(CATHODE) J45.1 R571.1(N1) R574.1(N1) R576.1 TP169.1(P1)
TRIG_IN_1: FB23.2 R700.2 U53.2(A)
TRIG_IN_2: FB24.2 R705.2 U54.2(A)
TRIG_IN_A: R698.1 R699.1 R700.1 R701.2 TP235.1(P1) U53.4(Y) ; also on sheet 2
TRIG_IN_B: R704.1 R705.1 TP236.1(P1) U54.4(Y) ; also on sheet 2
TRIG_OUT_1: FB25.2 R706.1 R707.1 TP237.1(P1) U55.4(Y)
TRIG_OUT_A: U55.2(A) ; also on sheet 10
TRIG_OUT_B: R772.2 U56.2(A) ; also on sheet 10
VBIAS: C317.1(P) TP167.1(P1) U35.99(DMD_VBIAS) ; also on sheet 5
VOFS: C319.1(P) TP173.1(P1) U35.98(DMD_VOFFSET) ; also on sheet 5
VRST: C312.1(P) D51.2(P2) TP165.1(P1) U35.100(DMD_VRESET) ; also on sheet 5
VRST_REF: TP166.1(P1) U35.1(DRST_VRST_REF)
N21777132: TP37.1(TP) U39.F14(GPIO_6)
N21777147: R145.2 U39.J14(GPIO_12)
N21777261: R117.2 R118.2 R119.2 R131.2 R208.1
N24657153: R148.2 U39.F15(GPIO_7)
N30691593: C342.1(P) R598.1(N1)
N30691665: C352.1(P) R602.1(N1)
N38575556: C309.2(N) R578.2(N2)
N41863342: TP80.1(TP) U40.H14(GPIO_10)
N41863344: TP81.1(TP) U40.H15(GPIO_11)
N41863346: TP82.1(TP) U40.J14(GPIO_12)
N41863348: TP83.1(TP) U40.J15(GPIO_13)
N41868707: TP75.1(TP) U40.E15(GPIO_5)
N41868709: TP76.1(TP) U40.F14(GPIO_6)
N41868711: TP77.1(TP) U40.F15(GPIO_7)
N41868713: TP78.1(TP) U40.G14(GPIO_8)
N41879171: R35.2 R36.2 R37.2 R132.2 R211.1
N42153930: C395.1 R696.1 R697.1 U53.5(PWR)
N42154043: ED24.1(CATHODE) FB25.1 J48.4
N42154045: ED27.1(CATHODE) FB22.1 J48.1 R771.2
N42154059: ED26.1(CATHODE) FB23.1 J48.2
N42154061: ED23.1(CATHODE) FB26.1 J48.5
N42154075: ED25.1(CATHODE) FB24.1 J48.3
N42154332: C396.1 R702.1 R703.1 U54.5(PWR)

Not connected (* = marked no-connect by the designer): U35 9(CH1_SWITCH_1)* 10(CH1_SWITCH_2)* 11(RLIM1_1)* 16(RLIM1_2)* 17(CH2_SWITCH_1)* 18(CH2_SWITCH_2)* 22(RLIM2_1)* 23(RLIM2_2)* 24(CH3_SWITCH_1)* 25(CH3_SWITCH_2)* 50(PWR7_BOOST)* 51(PWR7_FB)* 52(PWR7_VIN)* 53(PWR7_SWITCH)* 63(PWR6_SWITCH)* 64(PWR6_VIN)* 65(PWR6_BOOST)* 66(PWR6_FB)* 67(PWR5_VIN)* 68(PWR5_SWITCH)* 69(PWR5_BOOST)* 71(PWR5_FB)*; U40 A15(CMP_PWM)* B14(LED_SEL_1)* B15(LED_SEL_0)*

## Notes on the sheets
sheet 11
- MASTER
- SLAVE
- (MASTER ID)
- (SLAVE ID)
- (GPIO_8-PROJ_ON)
- (GPIO_9)
- (GPIO_11)
- (GPIO_12)
- <-- ITE6801_VSYNC
- MASTER
- --> MCU_P1.4
- --> DLPC3439 GPIO_5
- --> MCU_P1.5
- SLAVE
- Trigger Interface
- <-- DLPC3439 _TSTPT1
- <-- DLPC3439 _TSTPT2 or S_GPIO9
sheet 12
- TRP DMD:
- VOFS = 10V
- VBIAS = 18V
- MAX 16A OUTPUT
- VRST = -14V
- Red LED Connector
- Green LED Connector
- Blue LED Connector
- Connect the RLIM_K pins to SENSE
  Resistor(R595) with their own  traces.
  Also connect the  RLIM_BOT_K pins
  to the bottom of  the SENSE Resistor
  with their own traces.
- (DLPC3439_GPIO_11)
- Thermistor
  CONN
- DLPC3439 1.1V  Core
- (DLPC3439_GPIO_9)
- DLPC3439 1.8V & DMD VDD
- (DLPC3439_GPIO_12)
- DLPC3439 VINTF
